(* Logix 5000 project; controller SMD23E2_EDS_AOI_CompactLogix_RSLogix_V28 vendor 1 type 14 code 108 rev 28.11; software revision 28.00; part 2 of 4 *)

ADD_ON_INSTRUCTION AMCI_SMD23E2_Home_CW   (* revision 5.0, vendor AMCI, ExecuteEnableInFalse *)
// Revision note:
// Version 5.0 added the (hidden) ability to program the motor current and unlatched the error bit if the rung goes false.
VAR_INPUT
   Axis_Status_Bits : INT; {required}
   Type_0_for_standard_1_for_indexed : BOOL;
   Programmed_Speed : DINT; {required}
   Acceleration : INT; {required}
   Deceleration : INT; {required}
   motor_current : INT;
   Jerk : INT;
END_VAR
VAR_IN_OUT
   AMCI_SMD23E2_output_data : _000A:SMD23E2_788832CB:O:0; {required}
END_VAR
VAR_OUTPUT
   EN : BOOL; {access Read Only, visible}
   ER : BOOL; {visible}
END_VAR
VAR
   Upper_Result_X_1000 : DINT;
   command_data_block : INT[10];
        [1]   // Command Bits LSW
        [3]   // Lower Target Position
        [5]   // Lower Programmed Speed
        [0]   // Command Bits MSW
        [2]   // Upper Target Position
        [4]   // Upper Programmed Speed
END_VAR

ROUTINE EnableInFalse   (* ladder *)
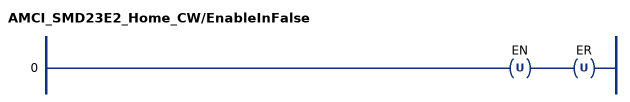
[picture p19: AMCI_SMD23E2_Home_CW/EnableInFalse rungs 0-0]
   0: OTU(EN)OTU(ER);
END_ROUTINE

ROUTINE Logic   (* ladder *)
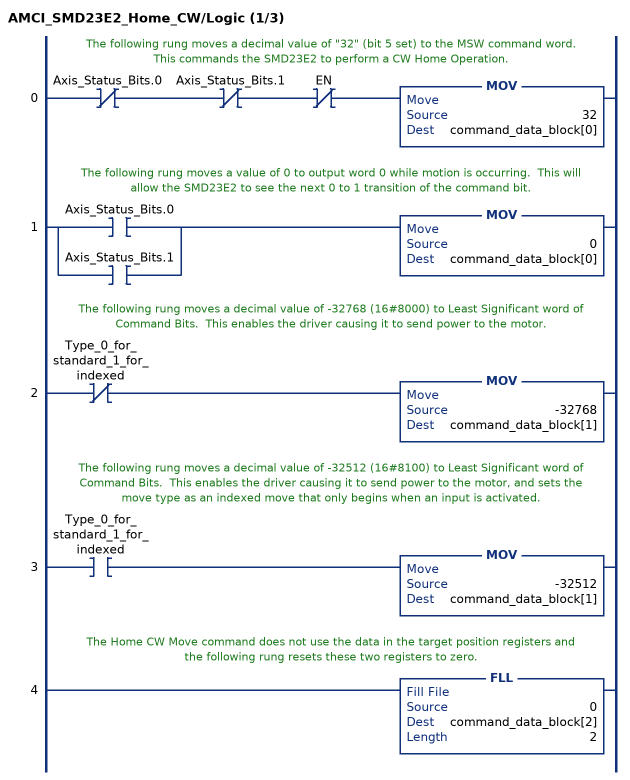
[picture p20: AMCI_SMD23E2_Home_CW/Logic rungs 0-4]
   // The following rung moves a decimal value of "32" (bit 5 set) to the MSW command word.  This commands the SMD23E2 to perform a CW Home Operation.
   0: XIO(Axis_Status_Bits.0)XIO(Axis_Status_Bits.1)XIO(EN)MOV(32,command_data_block[0]);
   // The following rung moves a value of 0 to output word 0 while motion is occurring.  This will allow the SMD23E2 to see the next 0 to 1 transition of the command bit.
   1: [XIC(Axis_Status_Bits.0) ,XIC(Axis_Status_Bits.1) ]MOV(0,command_data_block[0]);
   // The following rung moves a decimal value of -32768 (16#8000) to Least Significant word of Command Bits.  This enables the driver causing it to send power to the motor.
   2: XIO(Type_0_for_standard_1_for_indexed)MOV(-32768,command_data_block[1]);
   // The following rung moves a decimal value of -32512 (16#8100) to Least Significant word of Command Bits.  This enables the driver causing it to send power to the motor, and sets the move type as an indexed move that only begins when an input is activated.
   3: XIC(Type_0_for_standard_1_for_indexed)MOV(-32512,command_data_block[1]);
   // The Home CW Move command does not use the data in the target position registers and the following rung resets these two registers to zero.
   4: FLL(0,command_data_block[2],2);
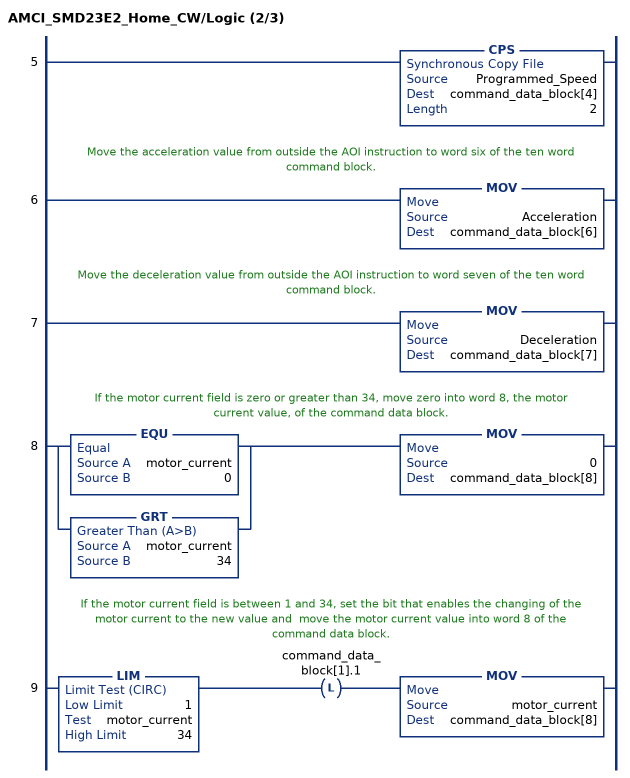
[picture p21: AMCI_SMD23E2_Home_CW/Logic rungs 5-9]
   5: CPS(Programmed_Speed,command_data_block[4],2);
   // Move the acceleration value from outside the AOI instruction to word six of the ten word command block.
   6: MOV(Acceleration,command_data_block[6]);
   // Move the deceleration value from outside the AOI instruction to word seven of the ten word command block.
   7: MOV(Deceleration,command_data_block[7]);
   // If the motor current field is zero or greater than 34, move zero into word 8, the motor current value, of the command data block.
   8: [EQU(motor_current,0) ,GRT(motor_current,34) ]MOV(0,command_data_block[8]);
   // If the motor current field is between 1 and 34, set the bit that enables the changing of the motor current to the new value and  move the motor current value into word 8 of the command data block.
   9: LIM(1,motor_current,34)OTL(command_data_block[1].1)MOV(motor_current,command_data_block[8]);
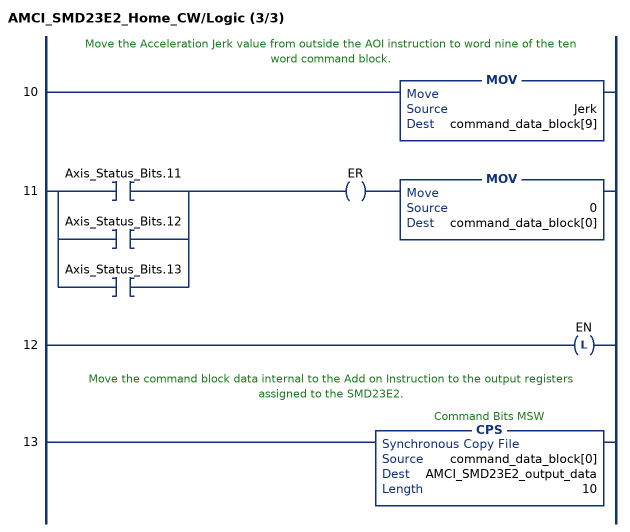
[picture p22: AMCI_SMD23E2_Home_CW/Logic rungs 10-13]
   // Move the Acceleration Jerk value from outside the AOI instruction to word nine of the ten word command block.
   10: MOV(Jerk,command_data_block[9]);
   11: [XIC(Axis_Status_Bits.11) ,XIC(Axis_Status_Bits.12) ,XIC(Axis_Status_Bits.13) ]OTE(ER)MOV(0,command_data_block[0]);
   12: OTL(EN);
   // Move the command block data internal to the Add on Instruction to the output registers assigned to the SMD23E2.
   13: CPS(command_data_block[0],AMCI_SMD23E2_output_data,10);
END_ROUTINE
END_ADD_ON_INSTRUCTION

ADD_ON_INSTRUCTION AMCI_SMD23E2_Immediate_Stop   (* revision 1.0, vendor AMCI *)
VAR_IN_OUT
   AMCI_SMD23E2_output_data : _000A:SMD23E2_788832CB:O:0; {required}
END_VAR
VAR
   command_data_block : INT[10];
        [1]   // Command Bits LSW
        [3]   // Lower Target Position
        [5]   // Lower Programmed Speed
        [0]   // Command Bits MSW
        [2]   // Upper Target Position
        [4]   // Upper Programmed Speed
END_VAR

ROUTINE Logic   (* ladder *)
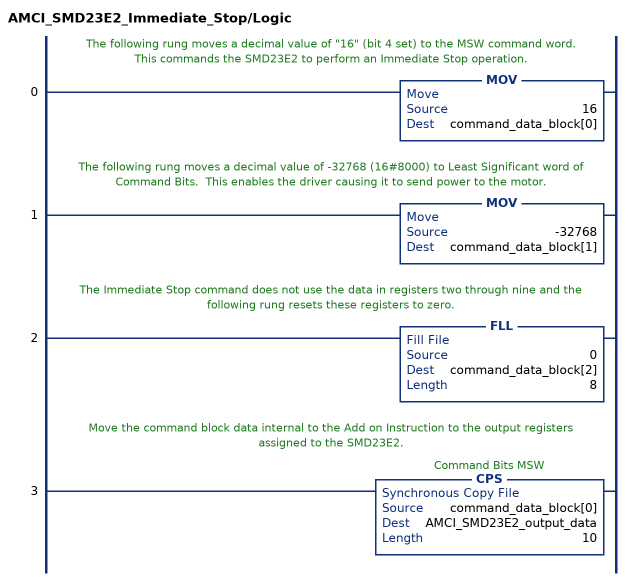
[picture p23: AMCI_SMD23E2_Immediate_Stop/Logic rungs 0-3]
   // The following rung moves a decimal value of "16" (bit 4 set) to the MSW command word.  This commands the SMD23E2 to perform an Immediate Stop operation.
   0: MOV(16,command_data_block[0]);
   // The following rung moves a decimal value of -32768 (16#8000) to Least Significant word of Command Bits.  This enables the driver causing it to send power to the motor.
   1: MOV(-32768,command_data_block[1]);
   // The Immediate Stop command does not use the data in registers two through nine and the following rung resets these registers to zero.
   2: FLL(0,command_data_block[2],8);
   // Move the command block data internal to the Add on Instruction to the output registers assigned to the SMD23E2.
   3: CPS(command_data_block[0],AMCI_SMD23E2_output_data,10);
END_ROUTINE
END_ADD_ON_INSTRUCTION

ADD_ON_INSTRUCTION AMCI_SMD23E2_Jog_CCW   (* revision 5.0, vendor AMCI, ExecuteEnableInFalse *)
// Revision note:
// Version 5.0 added the (hidden) ability to program the motor current and unlatched the error bit if the rung goes false.
VAR_INPUT
   Axis_Status_Bits : INT; {required}
   Programmed_Speed : DINT; {required}
   Acceleration : INT; {required}
   Deceleration : INT; {required}
   motor_current : INT;
   Jerk : INT;
END_VAR
VAR_OUTPUT
   EN : BOOL; {access Read Only, visible}
   Jog_CCW_Occurring : BOOL; {access Read Only, visible}
END_VAR
VAR_IN_OUT
   AMCI_SMD23E2_output_data : _000A:SMD23E2_788832CB:O:0; {required}
END_VAR
VAR_OUTPUT
   ER : BOOL; {access Read Only, visible}
END_VAR
VAR
   Upper_Result_X_1000 : DINT;
   command_data_block : INT[10];
        [1]   // Command Bits LSW
        [3]   // Lower Target Position
        [5]   // Lower Programmed Speed
        [0]   // Command Bits MSW
        [2]   // Upper Target Position
        [4]   // Upper Programmed Speed
END_VAR

ROUTINE EnableInFalse   (* ladder *)
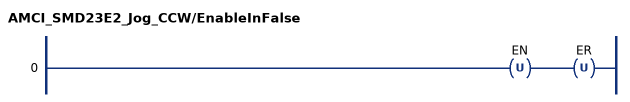
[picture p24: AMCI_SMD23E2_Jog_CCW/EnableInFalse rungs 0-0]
   0: OTU(EN)OTU(ER);
END_ROUTINE

ROUTINE Logic   (* ladder *)
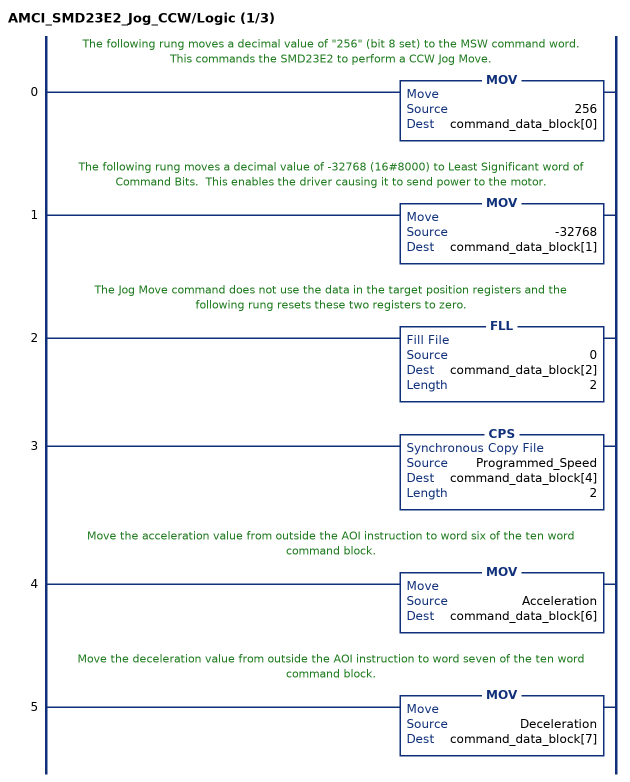
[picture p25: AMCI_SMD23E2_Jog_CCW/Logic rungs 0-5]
   // The following rung moves a decimal value of "256" (bit 8 set) to the MSW command word.  This commands the SMD23E2 to perform a CCW Jog Move.
   0: MOV(256,command_data_block[0]);
   // The following rung moves a decimal value of -32768 (16#8000) to Least Significant word of Command Bits.  This enables the driver causing it to send power to the motor.
   1: MOV(-32768,command_data_block[1]);
   // The Jog Move command does not use the data in the target position registers and the following rung resets these two registers to zero.
   2: FLL(0,command_data_block[2],2);
   3: CPS(Programmed_Speed,command_data_block[4],2);
   // Move the acceleration value from outside the AOI instruction to word six of the ten word command block.
   4: MOV(Acceleration,command_data_block[6]);
   // Move the deceleration value from outside the AOI instruction to word seven of the ten word command block.
   5: MOV(Deceleration,command_data_block[7]);
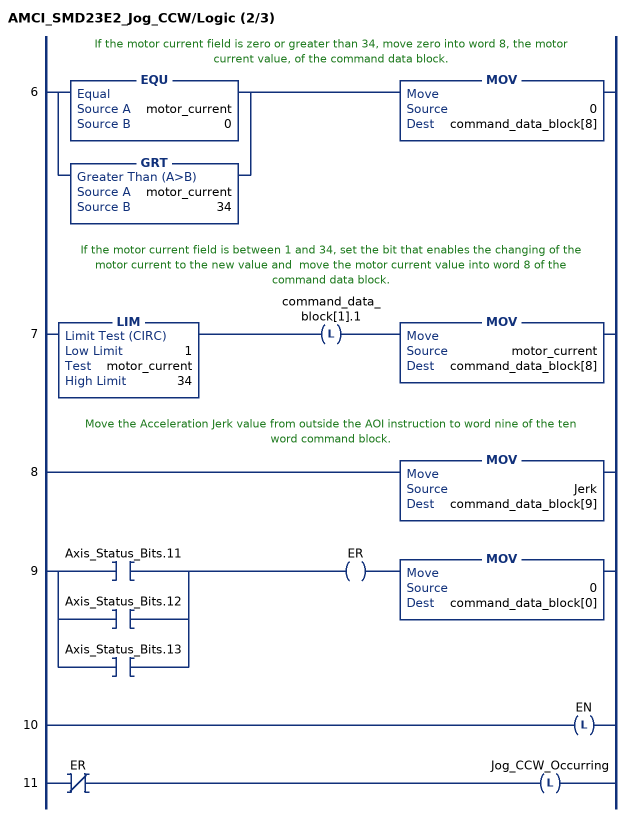
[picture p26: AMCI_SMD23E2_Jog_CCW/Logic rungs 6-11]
   // If the motor current field is zero or greater than 34, move zero into word 8, the motor current value, of the command data block.
   6: [EQU(motor_current,0) ,GRT(motor_current,34) ]MOV(0,command_data_block[8]);
   // If the motor current field is between 1 and 34, set the bit that enables the changing of the motor current to the new value and  move the motor current value into word 8 of the command data block.
   7: LIM(1,motor_current,34)OTL(command_data_block[1].1)MOV(motor_current,command_data_block[8]);
   // Move the Acceleration Jerk value from outside the AOI instruction to word nine of the ten word command block.
   8: MOV(Jerk,command_data_block[9]);
   9: [XIC(Axis_Status_Bits.11) ,XIC(Axis_Status_Bits.12) ,XIC(Axis_Status_Bits.13) ]OTE(ER)MOV(0,command_data_block[0]);
   10: OTL(EN);
   11: XIO(ER)OTL(Jog_CCW_Occurring);
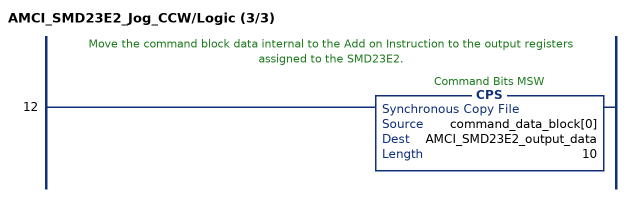
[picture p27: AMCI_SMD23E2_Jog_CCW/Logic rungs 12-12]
   // Move the command block data internal to the Add on Instruction to the output registers assigned to the SMD23E2.
   12: CPS(command_data_block[0],AMCI_SMD23E2_output_data,10);
END_ROUTINE
END_ADD_ON_INSTRUCTION

ADD_ON_INSTRUCTION AMCI_SMD23E2_Jog_CW   (* revision 5.0, vendor AMCI, ExecuteEnableInFalse *)
// Revision note:
// Version 5.0 added the (hidden) ability to program the motor current and unlatched the error bit if the rung goes false.
VAR_INPUT
   Axis_Status_Bits : INT; {required}
   Programmed_Speed : DINT; {required}
   Acceleration : INT; {required}
   Deceleration : INT; {required}
   motor_current : INT;
   Jerk : INT;
END_VAR
VAR_OUTPUT
   EN : BOOL; {access Read Only, visible}
   Jog_CW_Occurring : BOOL; {access Read Only, visible}
END_VAR
VAR_IN_OUT
   AMCI_SMD23E2_output_data : _000A:SMD23E2_788832CB:O:0; {required}
END_VAR
VAR_OUTPUT
   ER : BOOL; {access Read Only, visible}
END_VAR
VAR
   Upper_Result_X_1000 : DINT;
   command_data_block : INT[10];
        [1]   // Command Bits LSW
        [3]   // Lower Target Position
        [5]   // Lower Programmed Speed
        [0]   // Command Bits MSW
        [2]   // Upper Target Position
        [4]   // Upper Programmed Speed
END_VAR

ROUTINE EnableInFalse   (* ladder *)
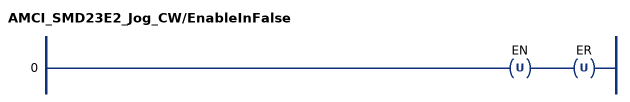
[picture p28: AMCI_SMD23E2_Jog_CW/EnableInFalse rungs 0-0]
   0: OTU(EN)OTU(ER);
END_ROUTINE

ROUTINE Logic   (* ladder *)
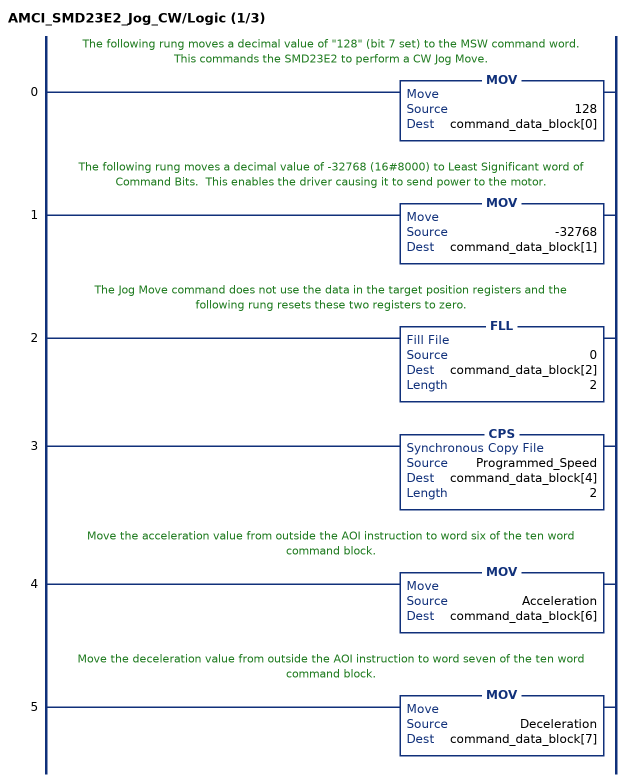
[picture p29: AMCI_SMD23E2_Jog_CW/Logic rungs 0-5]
   // The following rung moves a decimal value of "128" (bit 7 set) to the MSW command word.  This commands the SMD23E2 to perform a CW Jog Move.
   0: MOV(128,command_data_block[0]);
   // The following rung moves a decimal value of -32768 (16#8000) to Least Significant word of Command Bits.  This enables the driver causing it to send power to the motor.
   1: MOV(-32768,command_data_block[1]);
   // The Jog Move command does not use the data in the target position registers and the following rung resets these two registers to zero.
   2: FLL(0,command_data_block[2],2);
   3: CPS(Programmed_Speed,command_data_block[4],2);
   // Move the acceleration value from outside the AOI instruction to word six of the ten word command block.
   4: MOV(Acceleration,command_data_block[6]);
   // Move the deceleration value from outside the AOI instruction to word seven of the ten word command block.
   5: MOV(Deceleration,command_data_block[7]);
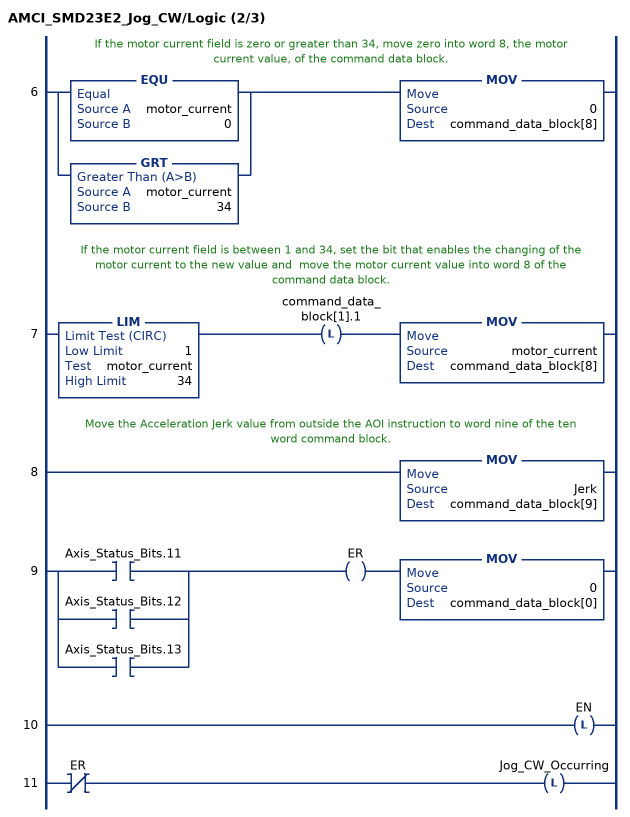
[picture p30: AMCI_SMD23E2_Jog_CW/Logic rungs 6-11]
   // If the motor current field is zero or greater than 34, move zero into word 8, the motor current value, of the command data block.
   6: [EQU(motor_current,0) ,GRT(motor_current,34) ]MOV(0,command_data_block[8]);
   // If the motor current field is between 1 and 34, set the bit that enables the changing of the motor current to the new value and  move the motor current value into word 8 of the command data block.
   7: LIM(1,motor_current,34)OTL(command_data_block[1].1)MOV(motor_current,command_data_block[8]);
   // Move the Acceleration Jerk value from outside the AOI instruction to word nine of the ten word command block.
   8: MOV(Jerk,command_data_block[9]);
   9: [XIC(Axis_Status_Bits.11) ,XIC(Axis_Status_Bits.12) ,XIC(Axis_Status_Bits.13) ]OTE(ER)MOV(0,command_data_block[0]);
   10: OTL(EN);
   11: XIO(ER)OTL(Jog_CW_Occurring);
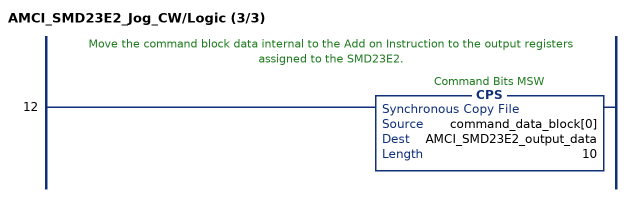
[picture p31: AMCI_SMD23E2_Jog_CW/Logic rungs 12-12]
   // Move the command block data internal to the Add on Instruction to the output registers assigned to the SMD23E2.
   12: CPS(command_data_block[0],AMCI_SMD23E2_output_data,10);
END_ROUTINE
END_ADD_ON_INSTRUCTION

ADD_ON_INSTRUCTION AMCI_SMD23E2_Preset_Encoder_Position   (* revision 1.0, vendor AMCI *)
VAR_INPUT
   save_in_flash_0_no_1_yes : BOOL; {required}
   Target_Position : DINT; {required}
END_VAR
VAR_IN_OUT
   AMCI_SMD23E2_output_data : _000A:SMD23E2_788832CB:O:0; {required}
END_VAR
VAR
   Upper_Result_X_1000 : DINT;
   command_data_block : INT[10];
        [1]   // Command Bits LSW
        [3]   // Lower Target Position
        [5]   // Lower Programmed Speed
        [0]   // Command Bits MSW
        [2]   // Upper Target Position
        [4]   // Upper Programmed Speed
END_VAR

ROUTINE Logic   (* ladder *)
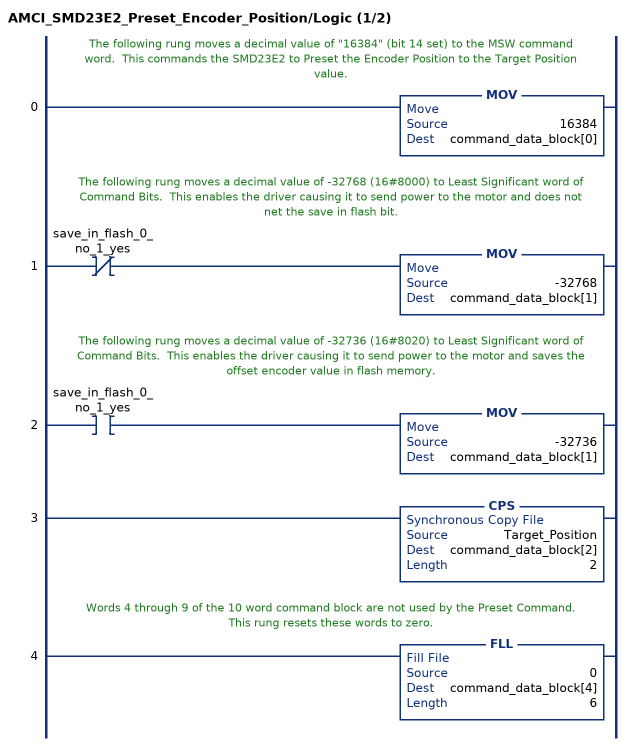
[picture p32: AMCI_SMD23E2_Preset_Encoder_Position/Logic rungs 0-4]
   // The following rung moves a decimal value of "16384" (bit 14 set) to the MSW command word.  This commands the SMD23E2 to Preset the Encoder Position to the Target Position value.
   0: MOV(16384,command_data_block[0]);
   // The following rung moves a decimal value of -32768 (16#8000) to Least Significant word of Command Bits.  This enables the driver causing it to send power to the motor and does not net the save in flash bit.
   1: XIO(save_in_flash_0_no_1_yes)MOV(-32768,command_data_block[1]);
   // The following rung moves a decimal value of -32736 (16#8020) to Least Significant word of Command Bits.  This enables the driver causing it to send power to the motor and saves the offset encoder value in flash memory.
   2: XIC(save_in_flash_0_no_1_yes)MOV(-32736,command_data_block[1]);
   3: CPS(Target_Position,command_data_block[2],2);
   // Words 4 through 9 of the 10 word command block are not used by the Preset Command.  This rung resets these words to zero.
   4: FLL(0,command_data_block[4],6);
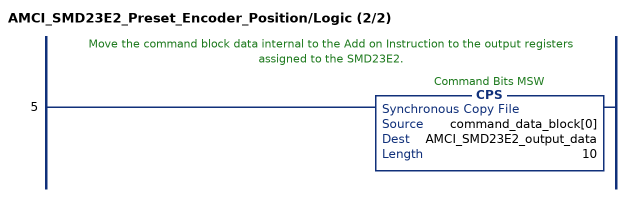
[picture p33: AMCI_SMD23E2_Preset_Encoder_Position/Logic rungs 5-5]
   // Move the command block data internal to the Add on Instruction to the output registers assigned to the SMD23E2.
   5: CPS(command_data_block[0],AMCI_SMD23E2_output_data,10);
END_ROUTINE
END_ADD_ON_INSTRUCTION

ADD_ON_INSTRUCTION AMCI_SMD23E2_Preset_Motor_Position   (* revision 1.0, vendor AMCI *)
VAR_INPUT
   Target_Position : DINT; {required}
END_VAR
VAR_IN_OUT
   AMCI_SMD23E2_output_data : _000A:SMD23E2_788832CB:O:0; {required}
END_VAR
VAR
   Upper_Result_X_1000 : DINT;
   command_data_block : INT[10];
        [1]   // Command Bits LSW
        [3]   // Lower Target Position
        [5]   // Lower Programmed Speed
        [2]   // Upper Target Position
        [4]   // Upper Programmed Speed
        [0]   // Command Bits MSW
END_VAR

ROUTINE Logic   (* ladder *)
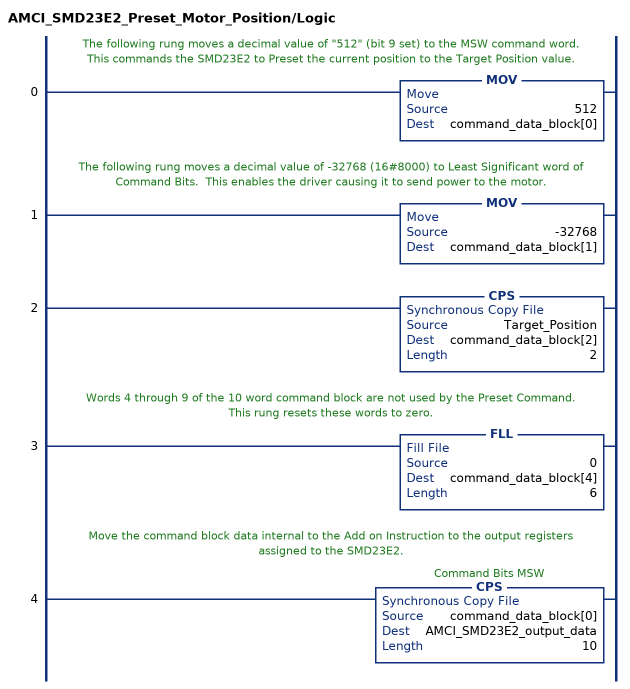
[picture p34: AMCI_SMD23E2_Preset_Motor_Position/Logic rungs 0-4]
   // The following rung moves a decimal value of "512" (bit 9 set) to the MSW command word.  This commands the SMD23E2 to Preset the current position to the Target Position value.
   0: MOV(512,command_data_block[0]);
   // The following rung moves a decimal value of -32768 (16#8000) to Least Significant word of Command Bits.  This enables the driver causing it to send power to the motor.
   1: MOV(-32768,command_data_block[1]);
   2: CPS(Target_Position,command_data_block[2],2);
   // Words 4 through 9 of the 10 word command block are not used by the Preset Command.  This rung resets these words to zero.
   3: FLL(0,command_data_block[4],6);
   // Move the command block data internal to the Add on Instruction to the output registers assigned to the SMD23E2.
   4: CPS(command_data_block[0],AMCI_SMD23E2_output_data,10);
END_ROUTINE
END_ADD_ON_INSTRUCTION

ADD_ON_INSTRUCTION AMCI_SMD23E2_Preset_Motor_to_Encoder   (* revision 1.0, vendor AMCI *)
VAR_IN_OUT
   AMCI_SMD23E2_output_data : _000A:SMD23E2_788832CB:O:0; {required}
END_VAR
VAR
   Upper_Result_X_1000 : DINT;
   command_data_block : INT[10];
        [1]   // Command Bits LSW
        [3]   // Lower Target Position
        [5]   // Lower Programmed Speed
        [0]   // Command Bits MSW
        [2]   // Upper Target Position
        [4]   // Upper Programmed Speed
END_VAR

ROUTINE Logic   (* ladder *)
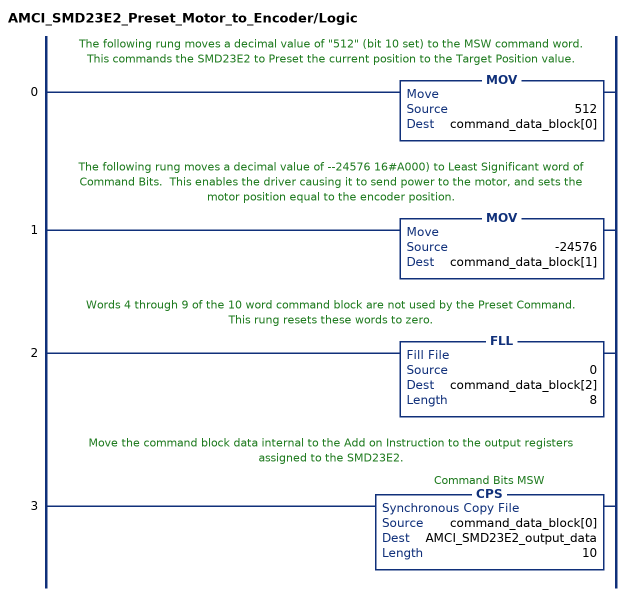
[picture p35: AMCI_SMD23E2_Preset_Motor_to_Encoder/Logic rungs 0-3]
   // The following rung moves a decimal value of "512" (bit 10 set) to the MSW command word.  This commands the SMD23E2 to Preset the current position to the Target Position value.
   0: MOV(512,command_data_block[0]);
   // The following rung moves a decimal value of --24576 16#A000) to Least Significant word of Command Bits.  This enables the driver causing it to send power to the motor, and sets the motor position equal to the encoder position.
   1: MOV(-24576,command_data_block[1]);
   // Words 4 through 9 of the 10 word command block are not used by the Preset Command.  This rung resets these words to zero.
   2: FLL(0,command_data_block[2],8);
   // Move the command block data internal to the Add on Instruction to the output registers assigned to the SMD23E2.
   3: CPS(command_data_block[0],AMCI_SMD23E2_output_data,10);
END_ROUTINE
END_ADD_ON_INSTRUCTION

ADD_ON_INSTRUCTION AMCI_SMD23E2_Program_Assembed_Move   (* revision 1.0, vendor AMCI *)
VAR_INPUT
   Axis_Status_Bits : INT; {required}
        .8   // set when SMD23E2 is in Assembled Move mode
        .9   // set when the SMD23E2 is ready to receive an assembled move segment
   Number_of_Segments : DINT; {required}
   Segment_1_Distance : DINT; {required}
   Segment_1_Programmed_Speed : DINT; {required}
   Segment_1_Acceleration : INT; {required}
   Segment_1_Deceleration : INT; {required}
   Segment_2_Distance : DINT; {required}
   Segment_2_Programmed_Speed : DINT; {required}
   Segment_2_Acceleration : INT; {required}
   Segment_2_Deceleration : INT; {required}
   Segment_3_Distance : DINT; {required}
   Segment_3_Programmed_Speed : DINT; {required}
   Segment_3_Acceleration : INT; {required}
   Segment_3_Deceleration : INT; {required}
   Segment_4_Distance : DINT; {required}
   Segment_4_Programmed_Speed : DINT; {required}
   Segment_4_Acceleration : INT; {required}
   Segment_4_Deceleration : INT; {required}
   Segment_5_Distance : DINT; {required}
   Segment_5_Programmed_Speed : DINT; {required}
   Segment_5_Acceleration : INT; {required}
   Segment_5_Deceleration : INT; {required}
   Segment_6_Distance : DINT; {required}
   Segment_6_Programmed_Speed : DINT; {required}
   Segment_6_Acceleration : INT; {required}
   Segment_6_Deceleration : INT; {required}
   Segment_7_Distance : DINT; {required}
   Segment_7_Programmed_Speed : DINT; {required}
   Segment_7_Acceleration : INT; {required}
   Segment_7_Deceleration : INT; {required}
   Segment_8_Distance : DINT; {required}
   Segment_8_Programmed_Speed : DINT; {required}
   Segment_8_Acceleration : INT; {required}
   Segment_8_Deceleration : INT; {required}
   Segment_9_Distance : DINT; {required}
   Segment_9_Programmed_Speed : DINT; {required}
   Segment_9_Acceleration : INT; {required}
   Segment_9_Deceleration : INT; {required}
   Segment_10_Distance : DINT; {required}
   Segment_10_Programmed_Speed : DINT; {required}
   Segment_10_Acceleration : INT; {required}
   Segment_10_Deceleration : INT; {required}
   Segment_11_Distance : DINT; {required}
   Segment_11_Programmed_Speed : DINT; {required}
   Segment_11_Acceleration : INT; {required}
   Segment_11_Deceleration : INT; {required}
   Segment_12_Distance : DINT; {required}
   Segment_12_Programmed_Speed : DINT; {required}
   Segment_12_Acceleration : INT; {required}
   Segment_12_Deceleration : INT; {required}
   Segment_13_Distance : DINT; {required}
   Segment_13_Programmed_Speed : DINT; {required}
   Segment_13_Acceleration : INT; {required}
   Segment_13_Deceleration : INT; {required}
   Segment_14_Distance : DINT; {required}
   Segment_14_Programmed_Speed : DINT; {required}
   Segment_14_Acceleration : INT; {required}
   Segment_14_Deceleration : INT; {required}
   Segment_15_Distance : DINT; {required}
   Segment_15_Programmed_Speed : DINT; {required}
   Segment_15_Acceleration : INT; {required}
   Segment_15_Deceleration : INT; {required}
   Segment_16_Distance : DINT; {required}
   Segment_16_Programmed_Speed : DINT; {required}
   Segment_16_Acceleration : INT; {required}
   Segment_16_Deceleration : INT; {required}
END_VAR
VAR_IN_OUT
   AMCI_SMD23E2_output_data : _000A:SMD23E2_788832CB:O:0; {required}
END_VAR
VAR_OUTPUT
   Assembled_Move_Programmed : BOOL; {access Read Only, visible}
END_VAR
VAR
   command_data_block : INT[10];
        [1]   // Command Bits LSW
        [5]   // Lower Programmed Speed
        [2]   // Upper Target Position
        [4]   // Upper Programmed Speed
        [3]   // Lower Target Position
        [0]   // Command Bits MSW
   Assembled_Move_setup : INT[10] := ([0] := 2048, [1] := -32768); {access None}
   Assembled_Move_counter : COUNTER := (PRE := 5); {access None}
        .ACC   // Controls which segment is sent to the SMD23E2
   comment_coil : BOOL; {access None}
END_VAR

ROUTINE Logic   (* ladder *)
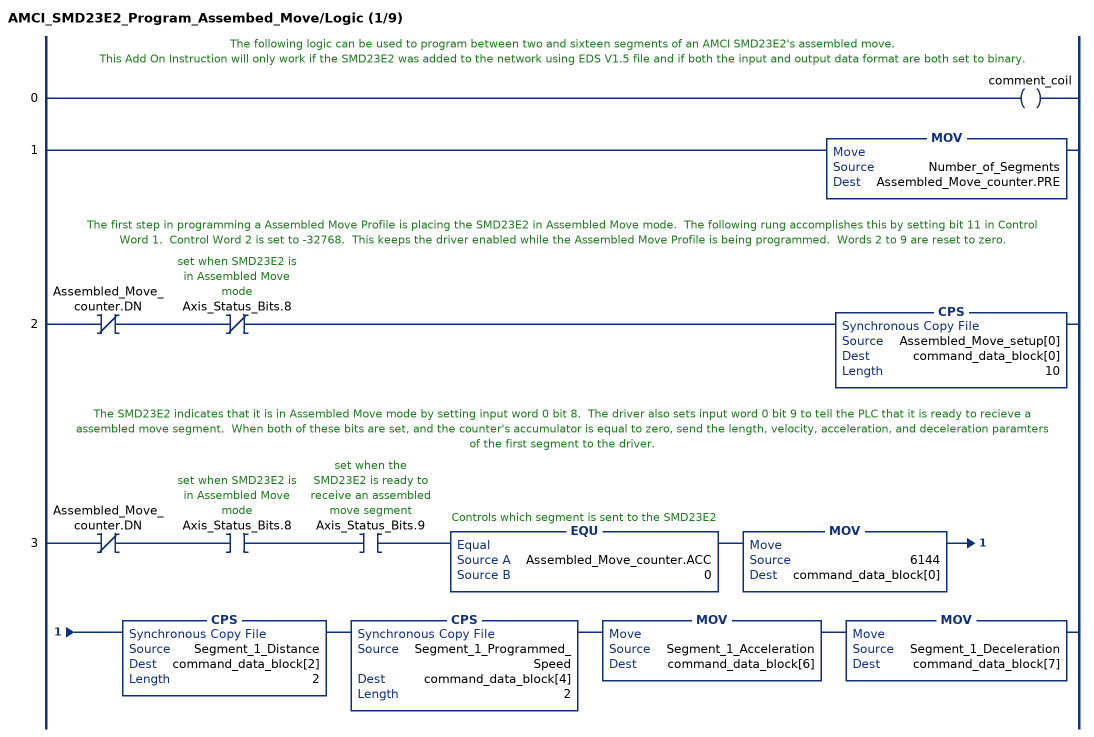
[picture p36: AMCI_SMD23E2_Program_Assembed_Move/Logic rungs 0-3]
   // The following logic can be used to program between two and sixteen segments of an AMCI SMD23E2's assembled move.
   // This Add On Instruction will only work if the SMD23E2 was added to the network using EDS V1.5 file and if both the input and output data format are both set to binary.
   0: OTE(comment_coil);
   1: MOV(Number_of_Segments,Assembled_Move_counter.PRE);
   // The first step in programming a Assembled Move Profile is placing the SMD23E2 in Assembled Move mode.  The following rung accomplishes this by setting bit 11 in Control Word 1.  Control Word 2 is set to -32768.  This keeps the driver enabled while the Assembled Move Profile is being programmed.  Words 2 to 9 are reset to zero.
   2: XIO(Assembled_Move_counter.DN)XIO(Axis_Status_Bits.8)CPS(Assembled_Move_setup[0],command_data_block[0],10);
   // The SMD23E2 indicates that it is in Assembled Move mode by setting input word 0 bit 8.  The driver also sets input word 0 bit 9 to tell the PLC that it is ready to recieve a assembled move segment.  When both of these bits are set, and the counter's accumulator is equal to zero, send the length, velocity, acceleration, and deceleration paramters of the first segment to the driver.
   3: XIO(Assembled_Move_counter.DN)XIC(Axis_Status_Bits.8)XIC(Axis_Status_Bits.9)EQU(Assembled_Move_counter.ACC,0)MOV(6144,command_data_block[0])CPS(Segment_1_Distance,command_data_block[2],2)CPS(Segment_1_Programmed_Speed,command_data_block[4],2)MOV(Segment_1_Acceleration,command_data_block[6])MOV(Segment_1_Deceleration,command_data_block[7]);
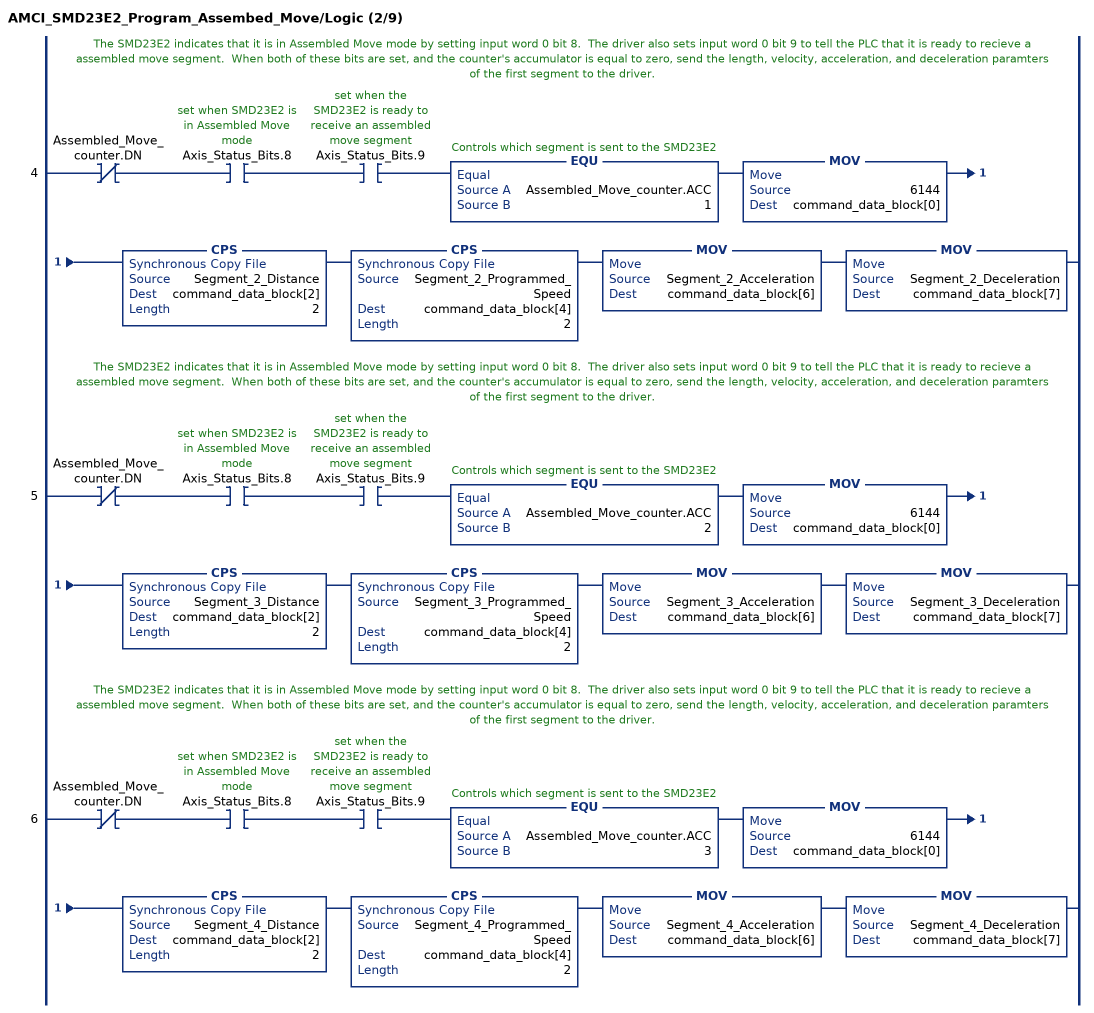
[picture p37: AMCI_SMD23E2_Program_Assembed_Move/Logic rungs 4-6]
   // The SMD23E2 indicates that it is in Assembled Move mode by setting input word 0 bit 8.  The driver also sets input word 0 bit 9 to tell the PLC that it is ready to recieve a assembled move segment.  When both of these bits are set, and the counter's accumulator is equal to zero, send the length, velocity, acceleration, and deceleration paramters of the first segment to the driver.
   4: XIO(Assembled_Move_counter.DN)XIC(Axis_Status_Bits.8)XIC(Axis_Status_Bits.9)EQU(Assembled_Move_counter.ACC,1)MOV(6144,command_data_block[0])CPS(Segment_2_Distance,command_data_block[2],2)CPS(Segment_2_Programmed_Speed,command_data_block[4],2)MOV(Segment_2_Acceleration,command_data_block[6])MOV(Segment_2_Deceleration,command_data_block[7]);
   // The SMD23E2 indicates that it is in Assembled Move mode by setting input word 0 bit 8.  The driver also sets input word 0 bit 9 to tell the PLC that it is ready to recieve a assembled move segment.  When both of these bits are set, and the counter's accumulator is equal to zero, send the length, velocity, acceleration, and deceleration paramters of the first segment to the driver.
   5: XIO(Assembled_Move_counter.DN)XIC(Axis_Status_Bits.8)XIC(Axis_Status_Bits.9)EQU(Assembled_Move_counter.ACC,2)MOV(6144,command_data_block[0])CPS(Segment_3_Distance,command_data_block[2],2)CPS(Segment_3_Programmed_Speed,command_data_block[4],2)MOV(Segment_3_Acceleration,command_data_block[6])MOV(Segment_3_Deceleration,command_data_block[7]);
   // The SMD23E2 indicates that it is in Assembled Move mode by setting input word 0 bit 8.  The driver also sets input word 0 bit 9 to tell the PLC that it is ready to recieve a assembled move segment.  When both of these bits are set, and the counter's accumulator is equal to zero, send the length, velocity, acceleration, and deceleration paramters of the first segment to the driver.
   6: XIO(Assembled_Move_counter.DN)XIC(Axis_Status_Bits.8)XIC(Axis_Status_Bits.9)EQU(Assembled_Move_counter.ACC,3)MOV(6144,command_data_block[0])CPS(Segment_4_Distance,command_data_block[2],2)CPS(Segment_4_Programmed_Speed,command_data_block[4],2)MOV(Segment_4_Acceleration,command_data_block[6])MOV(Segment_4_Deceleration,command_data_block[7]);
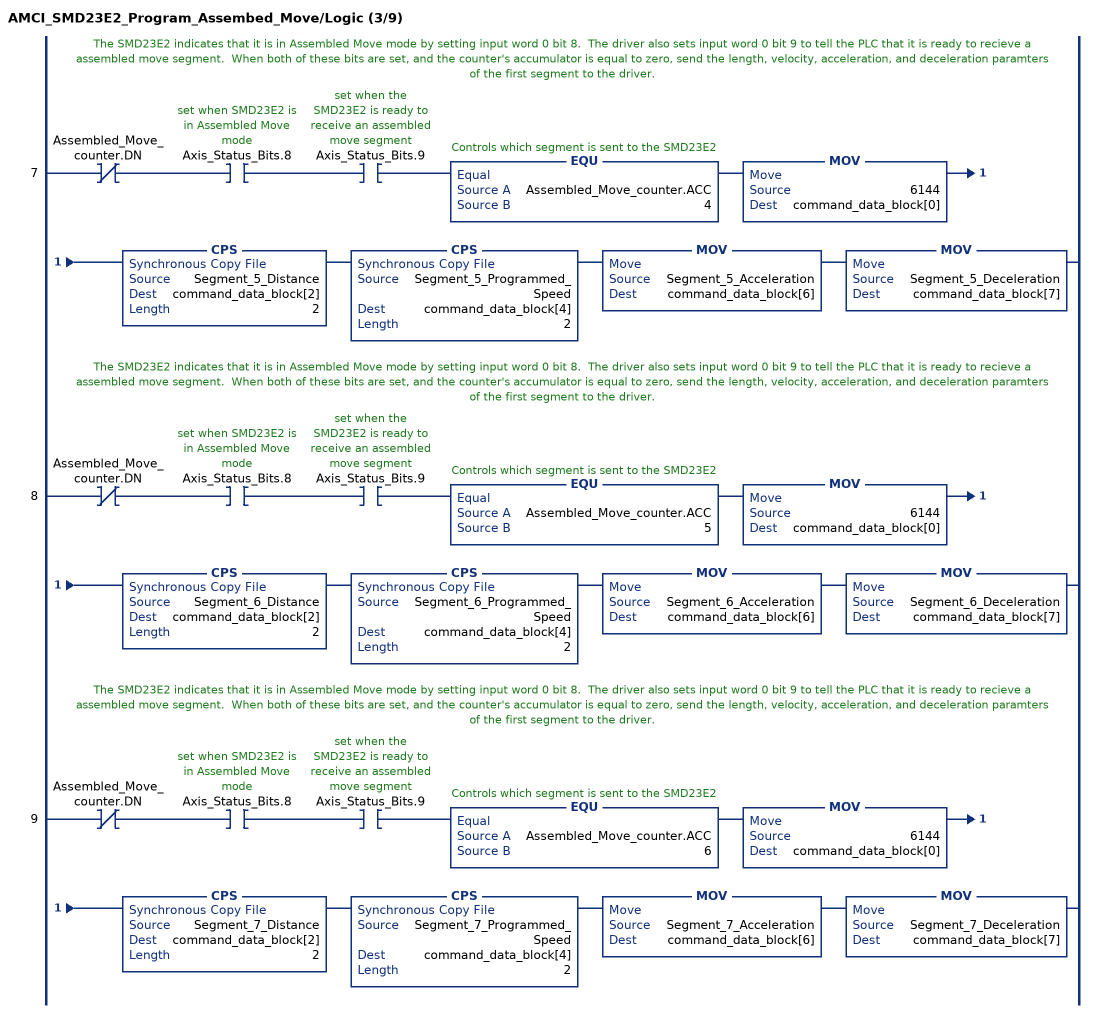
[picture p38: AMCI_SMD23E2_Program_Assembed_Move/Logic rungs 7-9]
   // The SMD23E2 indicates that it is in Assembled Move mode by setting input word 0 bit 8.  The driver also sets input word 0 bit 9 to tell the PLC that it is ready to recieve a assembled move segment.  When both of these bits are set, and the counter's accumulator is equal to zero, send the length, velocity, acceleration, and deceleration paramters of the first segment to the driver.
   7: XIO(Assembled_Move_counter.DN)XIC(Axis_Status_Bits.8)XIC(Axis_Status_Bits.9)EQU(Assembled_Move_counter.ACC,4)MOV(6144,command_data_block[0])CPS(Segment_5_Distance,command_data_block[2],2)CPS(Segment_5_Programmed_Speed,command_data_block[4],2)MOV(Segment_5_Acceleration,command_data_block[6])MOV(Segment_5_Deceleration,command_data_block[7]);
   // The SMD23E2 indicates that it is in Assembled Move mode by setting input word 0 bit 8.  The driver also sets input word 0 bit 9 to tell the PLC that it is ready to recieve a assembled move segment.  When both of these bits are set, and the counter's accumulator is equal to zero, send the length, velocity, acceleration, and deceleration paramters of the first segment to the driver.
   8: XIO(Assembled_Move_counter.DN)XIC(Axis_Status_Bits.8)XIC(Axis_Status_Bits.9)EQU(Assembled_Move_counter.ACC,5)MOV(6144,command_data_block[0])CPS(Segment_6_Distance,command_data_block[2],2)CPS(Segment_6_Programmed_Speed,command_data_block[4],2)MOV(Segment_6_Acceleration,command_data_block[6])MOV(Segment_6_Deceleration,command_data_block[7]);
   // The SMD23E2 indicates that it is in Assembled Move mode by setting input word 0 bit 8.  The driver also sets input word 0 bit 9 to tell the PLC that it is ready to recieve a assembled move segment.  When both of these bits are set, and the counter's accumulator is equal to zero, send the length, velocity, acceleration, and deceleration paramters of the first segment to the driver.
   9: XIO(Assembled_Move_counter.DN)XIC(Axis_Status_Bits.8)XIC(Axis_Status_Bits.9)EQU(Assembled_Move_counter.ACC,6)MOV(6144,command_data_block[0])CPS(Segment_7_Distance,command_data_block[2],2)CPS(Segment_7_Programmed_Speed,command_data_block[4],2)MOV(Segment_7_Acceleration,command_data_block[6])MOV(Segment_7_Deceleration,command_data_block[7]);
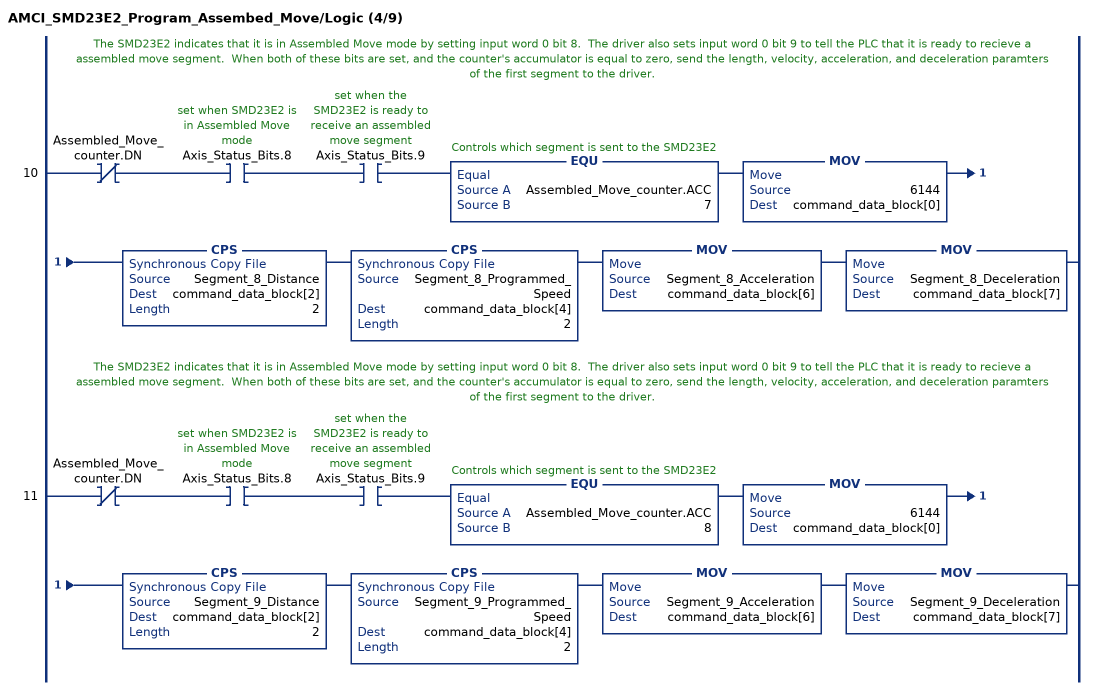
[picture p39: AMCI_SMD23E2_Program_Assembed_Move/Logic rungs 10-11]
   // The SMD23E2 indicates that it is in Assembled Move mode by setting input word 0 bit 8.  The driver also sets input word 0 bit 9 to tell the PLC that it is ready to recieve a assembled move segment.  When both of these bits are set, and the counter's accumulator is equal to zero, send the length, velocity, acceleration, and deceleration paramters of the first segment to the driver.
   10: XIO(Assembled_Move_counter.DN)XIC(Axis_Status_Bits.8)XIC(Axis_Status_Bits.9)EQU(Assembled_Move_counter.ACC,7)MOV(6144,command_data_block[0])CPS(Segment_8_Distance,command_data_block[2],2)CPS(Segment_8_Programmed_Speed,command_data_block[4],2)MOV(Segment_8_Acceleration,command_data_block[6])MOV(Segment_8_Deceleration,command_data_block[7]);
   // The SMD23E2 indicates that it is in Assembled Move mode by setting input word 0 bit 8.  The driver also sets input word 0 bit 9 to tell the PLC that it is ready to recieve a assembled move segment.  When both of these bits are set, and the counter's accumulator is equal to zero, send the length, velocity, acceleration, and deceleration paramters of the first segment to the driver.
   11: XIO(Assembled_Move_counter.DN)XIC(Axis_Status_Bits.8)XIC(Axis_Status_Bits.9)EQU(Assembled_Move_counter.ACC,8)MOV(6144,command_data_block[0])CPS(Segment_9_Distance,command_data_block[2],2)CPS(Segment_9_Programmed_Speed,command_data_block[4],2)MOV(Segment_9_Acceleration,command_data_block[6])MOV(Segment_9_Deceleration,command_data_block[7]);
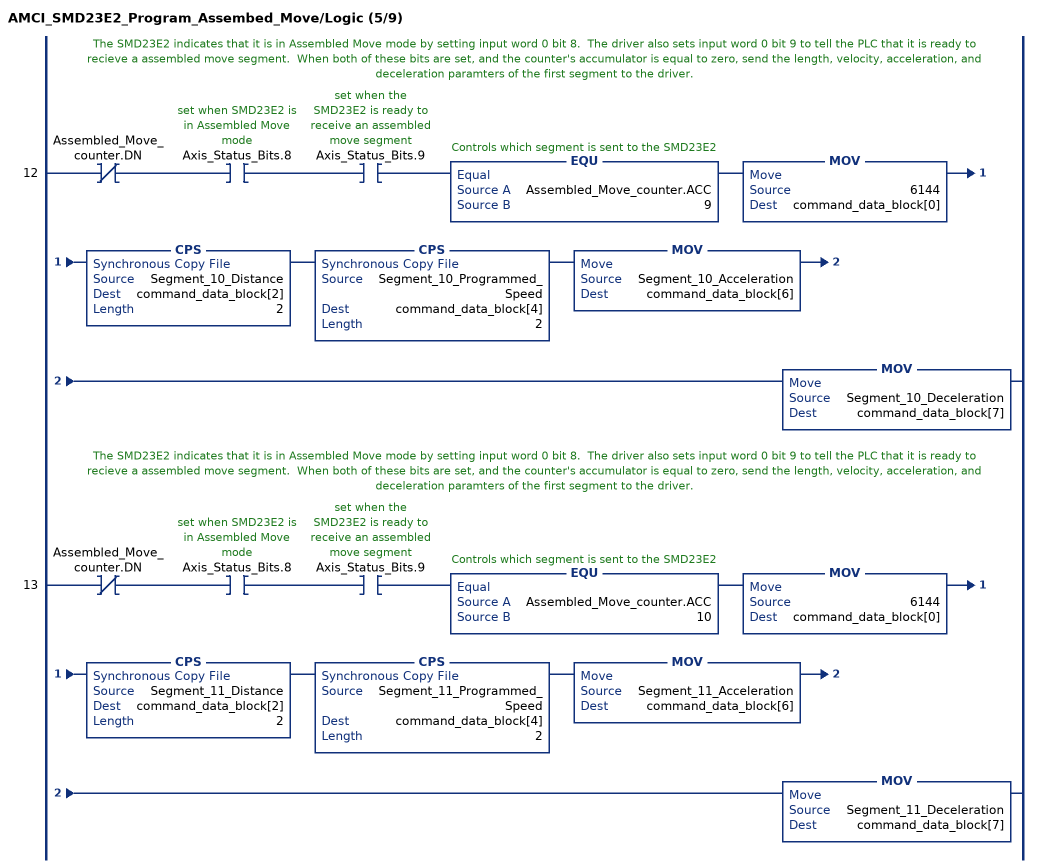
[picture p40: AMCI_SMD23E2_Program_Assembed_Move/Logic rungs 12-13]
   // The SMD23E2 indicates that it is in Assembled Move mode by setting input word 0 bit 8.  The driver also sets input word 0 bit 9 to tell the PLC that it is ready to recieve a assembled move segment.  When both of these bits are set, and the counter's accumulator is equal to zero, send the length, velocity, acceleration, and deceleration paramters of the first segment to the driver.
   12: XIO(Assembled_Move_counter.DN)XIC(Axis_Status_Bits.8)XIC(Axis_Status_Bits.9)EQU(Assembled_Move_counter.ACC,9)MOV(6144,command_data_block[0])CPS(Segment_10_Distance,command_data_block[2],2)CPS(Segment_10_Programmed_Speed,command_data_block[4],2)MOV(Segment_10_Acceleration,command_data_block[6])MOV(Segment_10_Deceleration,command_data_block[7]);
   // The SMD23E2 indicates that it is in Assembled Move mode by setting input word 0 bit 8.  The driver also sets input word 0 bit 9 to tell the PLC that it is ready to recieve a assembled move segment.  When both of these bits are set, and the counter's accumulator is equal to zero, send the length, velocity, acceleration, and deceleration paramters of the first segment to the driver.
   13: XIO(Assembled_Move_counter.DN)XIC(Axis_Status_Bits.8)XIC(Axis_Status_Bits.9)EQU(Assembled_Move_counter.ACC,10)MOV(6144,command_data_block[0])CPS(Segment_11_Distance,command_data_block[2],2)CPS(Segment_11_Programmed_Speed,command_data_block[4],2)MOV(Segment_11_Acceleration,command_data_block[6])MOV(Segment_11_Deceleration,command_data_block[7]);
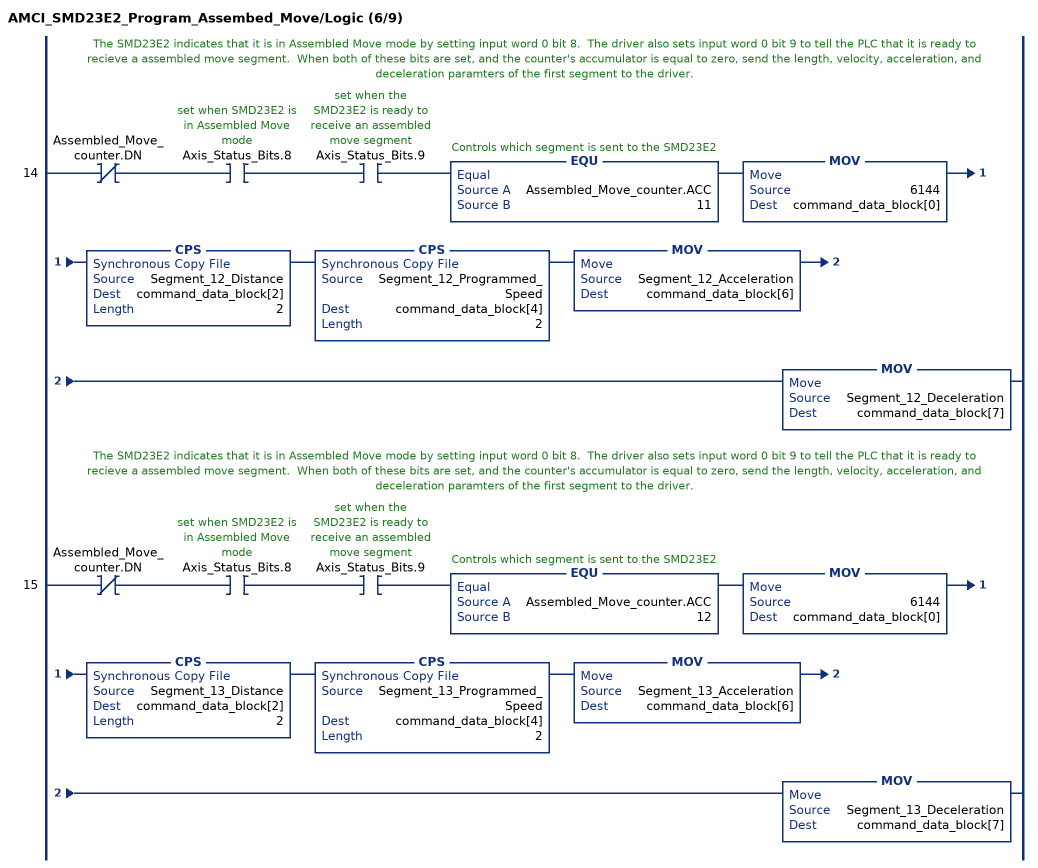
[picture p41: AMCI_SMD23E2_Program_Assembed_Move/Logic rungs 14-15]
   // The SMD23E2 indicates that it is in Assembled Move mode by setting input word 0 bit 8.  The driver also sets input word 0 bit 9 to tell the PLC that it is ready to recieve a assembled move segment.  When both of these bits are set, and the counter's accumulator is equal to zero, send the length, velocity, acceleration, and deceleration paramters of the first segment to the driver.
   14: XIO(Assembled_Move_counter.DN)XIC(Axis_Status_Bits.8)XIC(Axis_Status_Bits.9)EQU(Assembled_Move_counter.ACC,11)MOV(6144,command_data_block[0])CPS(Segment_12_Distance,command_data_block[2],2)CPS(Segment_12_Programmed_Speed,command_data_block[4],2)MOV(Segment_12_Acceleration,command_data_block[6])MOV(Segment_12_Deceleration,command_data_block[7]);
   // The SMD23E2 indicates that it is in Assembled Move mode by setting input word 0 bit 8.  The driver also sets input word 0 bit 9 to tell the PLC that it is ready to recieve a assembled move segment.  When both of these bits are set, and the counter's accumulator is equal to zero, send the length, velocity, acceleration, and deceleration paramters of the first segment to the driver.
   15: XIO(Assembled_Move_counter.DN)XIC(Axis_Status_Bits.8)XIC(Axis_Status_Bits.9)EQU(Assembled_Move_counter.ACC,12)MOV(6144,command_data_block[0])CPS(Segment_13_Distance,command_data_block[2],2)CPS(Segment_13_Programmed_Speed,command_data_block[4],2)MOV(Segment_13_Acceleration,command_data_block[6])MOV(Segment_13_Deceleration,command_data_block[7]);
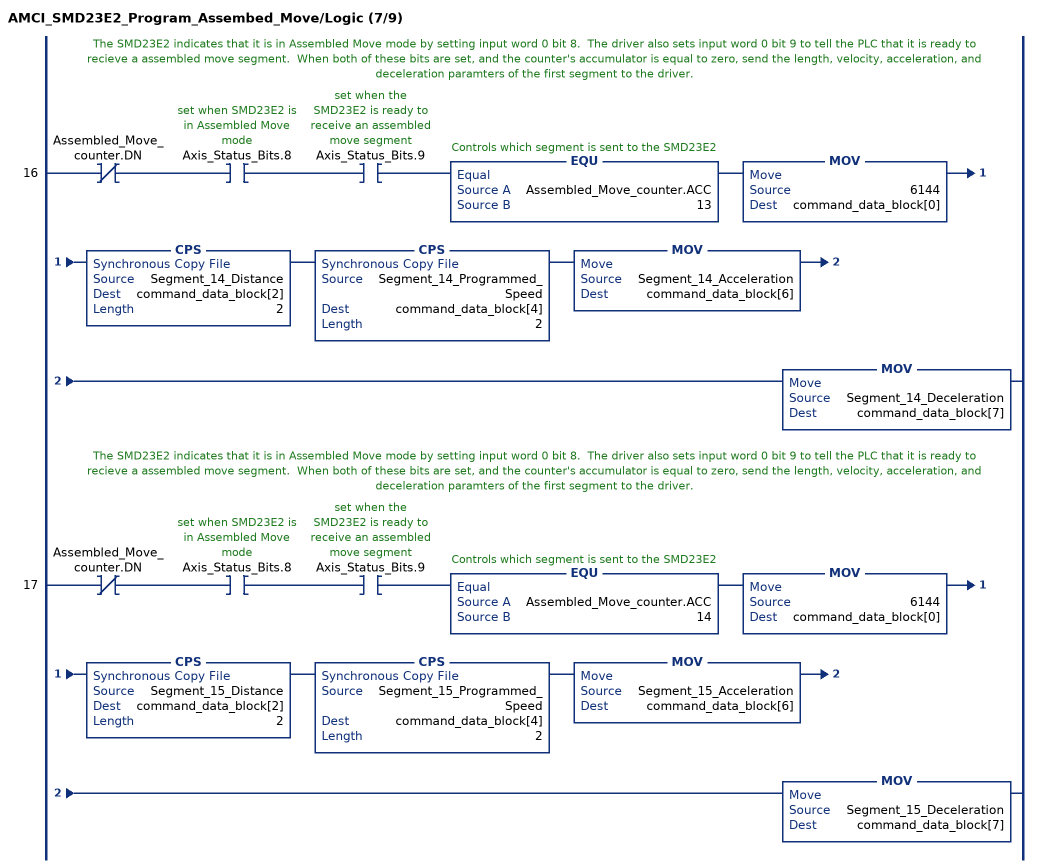
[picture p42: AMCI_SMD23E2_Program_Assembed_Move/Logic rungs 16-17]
   // The SMD23E2 indicates that it is in Assembled Move mode by setting input word 0 bit 8.  The driver also sets input word 0 bit 9 to tell the PLC that it is ready to recieve a assembled move segment.  When both of these bits are set, and the counter's accumulator is equal to zero, send the length, velocity, acceleration, and deceleration paramters of the first segment to the driver.
   16: XIO(Assembled_Move_counter.DN)XIC(Axis_Status_Bits.8)XIC(Axis_Status_Bits.9)EQU(Assembled_Move_counter.ACC,13)MOV(6144,command_data_block[0])CPS(Segment_14_Distance,command_data_block[2],2)CPS(Segment_14_Programmed_Speed,command_data_block[4],2)MOV(Segment_14_Acceleration,command_data_block[6])MOV(Segment_14_Deceleration,command_data_block[7]);
   // The SMD23E2 indicates that it is in Assembled Move mode by setting input word 0 bit 8.  The driver also sets input word 0 bit 9 to tell the PLC that it is ready to recieve a assembled move segment.  When both of these bits are set, and the counter's accumulator is equal to zero, send the length, velocity, acceleration, and deceleration paramters of the first segment to the driver.
   17: XIO(Assembled_Move_counter.DN)XIC(Axis_Status_Bits.8)XIC(Axis_Status_Bits.9)EQU(Assembled_Move_counter.ACC,14)MOV(6144,command_data_block[0])CPS(Segment_15_Distance,command_data_block[2],2)CPS(Segment_15_Programmed_Speed,command_data_block[4],2)MOV(Segment_15_Acceleration,command_data_block[6])MOV(Segment_15_Deceleration,command_data_block[7]);
(* Logix 5000 project; controller SMD23E2_EDS_AOI_CompactLogix_RSLogix_V28 vendor 1 type 14 code 108 rev 28.11; software revision 28.00; part 3 of 4 *)
(* tags used below, declared in another part *)
   Segment_16_Distance : DINT;
   Segment_16_Programmed_Speed : DINT;
   Segment_16_Acceleration : INT;
   Segment_16_Deceleration : INT;
   Assembled_Move_Programmed : BOOL;
   Assembled_Move_counter : COUNTER;
(* AMCI_SMD23E2_Program_Assembed_Move, continued *)

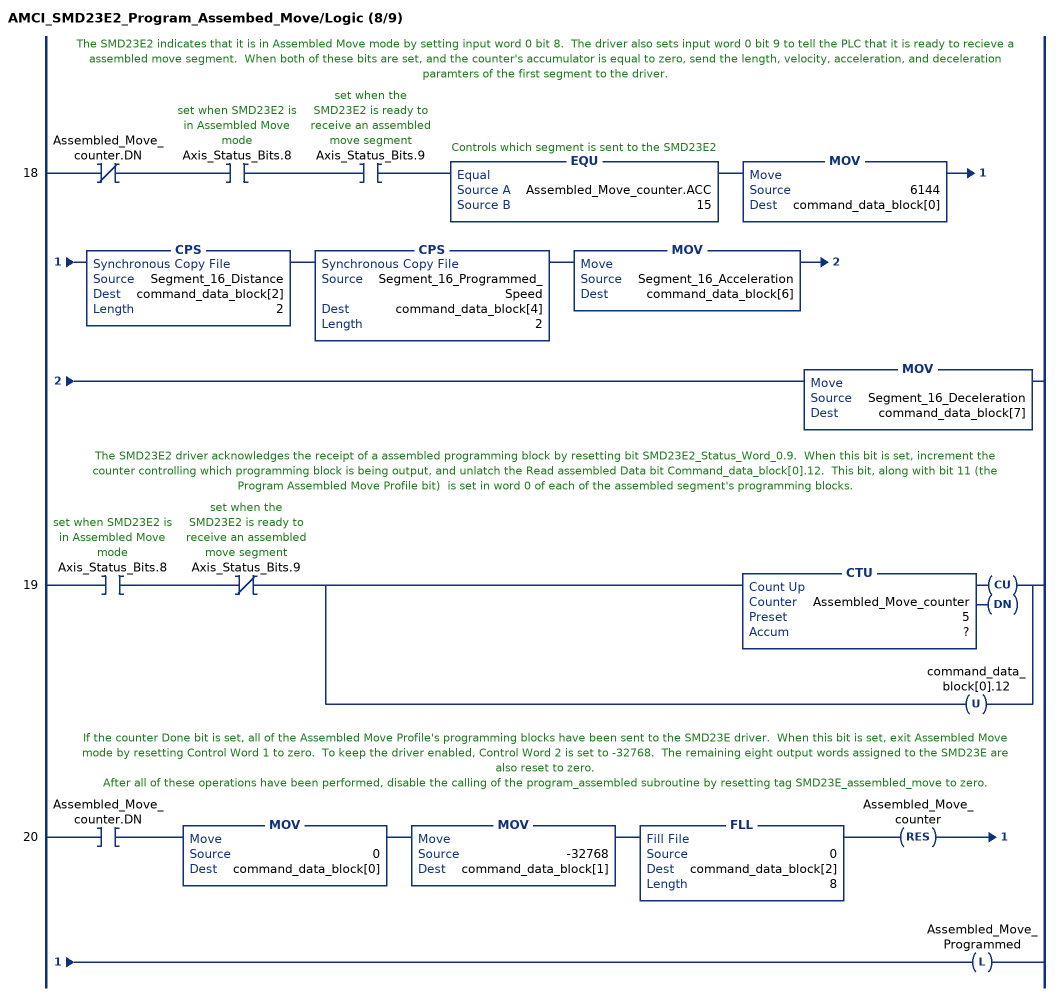
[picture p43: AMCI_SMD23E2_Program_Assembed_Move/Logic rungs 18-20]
   // The SMD23E2 indicates that it is in Assembled Move mode by setting input word 0 bit 8.  The driver also sets input word 0 bit 9 to tell the PLC that it is ready to recieve a assembled move segment.  When both of these bits are set, and the counter's accumulator is equal to zero, send the length, velocity, acceleration, and deceleration paramters of the first segment to the driver.
   18: XIO(Assembled_Move_counter.DN)XIC(Axis_Status_Bits.8)XIC(Axis_Status_Bits.9)EQU(Assembled_Move_counter.ACC,15)MOV(6144,command_data_block[0])CPS(Segment_16_Distance,command_data_block[2],2)CPS(Segment_16_Programmed_Speed,command_data_block[4],2)MOV(Segment_16_Acceleration,command_data_block[6])MOV(Segment_16_Deceleration,command_data_block[7]);
   // The SMD23E2 driver acknowledges the receipt of a assembled programming block by resetting bit SMD23E2_Status_Word_0.9.  When this bit is set, increment the counter controlling which programming block is being output, and unlatch the Read assembled Data bit Command_data_block[0].12.  This bit, along with bit 11 (the Program Assembled Move Profile bit)  is set in word 0 of each of the assembled segment's programming blocks.
   19: XIC(Axis_Status_Bits.8)XIO(Axis_Status_Bits.9)[CTU(Assembled_Move_counter,?,?) ,OTU(command_data_block[0].12) ];
   // If the counter Done bit is set, all of the Assembled Move Profile's programming blocks have been sent to the SMD23E driver.  When this bit is set, exit Assembled Move mode by resetting Control Word 1 to zero.  To keep the driver enabled, Control Word 2 is set to -32768.  The remaining eight output words assigned to the SMD23E are also reset to zero.
   // After all of these operations have been performed, disable the calling of the program_assembled subroutine by resetting tag SMD23E_assembled_move to zero.
   20: XIC(Assembled_Move_counter.DN)MOV(0,command_data_block[0])MOV(-32768,command_data_block[1])FLL(0,command_data_block[2],8)RES(Assembled_Move_counter)OTL(Assembled_Move_Programmed);
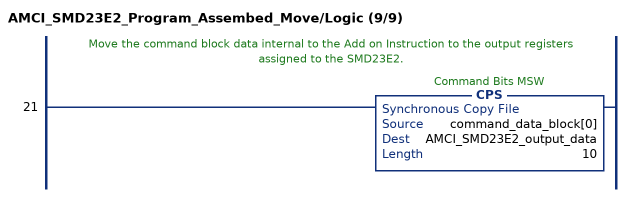
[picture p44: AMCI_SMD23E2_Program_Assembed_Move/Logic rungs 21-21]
   // Move the command block data internal to the Add on Instruction to the output registers assigned to the SMD23E2.
   21: CPS(command_data_block[0],AMCI_SMD23E2_output_data,10);
END_ROUTINE
END_ADD_ON_INSTRUCTION

ADD_ON_INSTRUCTION AMCI_SMD23E2_Program_Motor_Current   (* revision 1.0, vendor AMCI *)
VAR_INPUT
   Motor_Current : INT; {required}
END_VAR
VAR_IN_OUT
   AMCI_SMD23E2_output_data : _000A:SMD23E2_788832CB:O:0; {required}
END_VAR
VAR
   Upper_Result_X_1000 : DINT;
   command_data_block : INT[10];
        [1]   // Command Bits LSW
        [3]   // Lower Target Position
        [5]   // Lower Programmed Speed
        [0]   // Command Bits MSW
        [2]   // Upper Target Position
        [4]   // Upper Programmed Speed
END_VAR

ROUTINE Logic   (* ladder *)
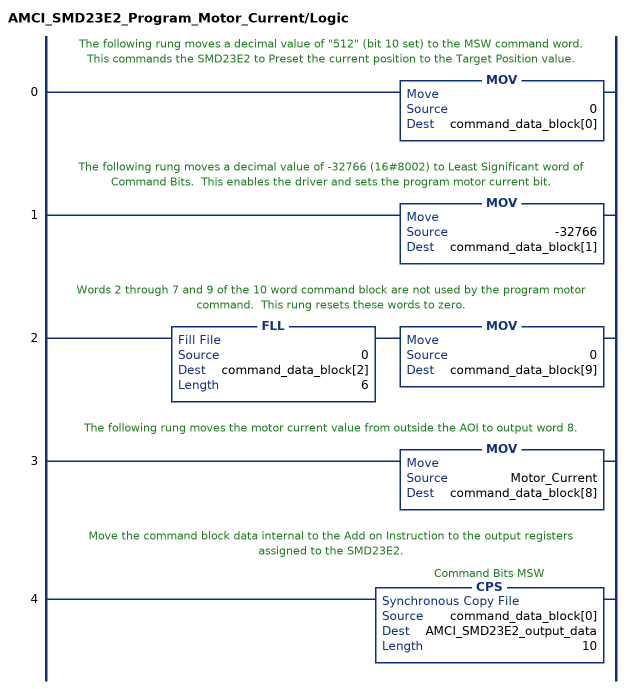
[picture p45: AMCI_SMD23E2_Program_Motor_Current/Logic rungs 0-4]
   // The following rung moves a decimal value of "512" (bit 10 set) to the MSW command word.  This commands the SMD23E2 to Preset the current position to the Target Position value.
   0: MOV(0,command_data_block[0]);
   // The following rung moves a decimal value of -32766 (16#8002) to Least Significant word of Command Bits.  This enables the driver and sets the program motor current bit.
   1: MOV(-32766,command_data_block[1]);
   // Words 2 through 7 and 9 of the 10 word command block are not used by the program motor command.  This rung resets these words to zero.
   2: FLL(0,command_data_block[2],6)MOV(0,command_data_block[9]);
   // The following rung moves the motor current value from outside the AOI to output word 8.
   3: MOV(Motor_Current,command_data_block[8]);
   // Move the command block data internal to the Add on Instruction to the output registers assigned to the SMD23E2.
   4: CPS(command_data_block[0],AMCI_SMD23E2_output_data,10);
END_ROUTINE
END_ADD_ON_INSTRUCTION

ADD_ON_INSTRUCTION AMCI_SMD23E2_Registration_Move_CCW   (* revision 5.0, vendor AMCI, ExecuteEnableInFalse *)
// Revision note:
// Version 5.0  unlatches the error bit if the rung goes false.
VAR_INPUT
   Axis_Status_Bits : INT; {required}
   Type_0_for_standard_1_for_indexed : BOOL;
   Stopping_Distance : DINT; {required}
   Programmed_Speed : DINT; {required}
   Acceleration : INT; {required}
   Deceleration : INT; {required}
   Minimum_Registration_Move_Distance : DINT; {required}
END_VAR
VAR_OUTPUT
   EN : BOOL; {access Read Only, visible}
   Registration_Move_CCW_Occurring : BOOL; {access Read Only, visible}
END_VAR
VAR_IN_OUT
   AMCI_SMD23E2_output_data : _000A:SMD23E2_788832CB:O:0; {required}
END_VAR
VAR_OUTPUT
   ER : BOOL; {access Read Only, visible}
END_VAR
VAR
   Upper_Result_X_1000 : DINT;
   command_data_block : INT[10];
        [1]   // Command Bits LSW
        [3]   // Lower Target Position
        [5]   // Lower Programmed Speed
        [0]   // Command Bits MSW
        [2]   // Upper Target Position
        [4]   // Upper Programmed Speed
END_VAR

ROUTINE EnableInFalse   (* ladder *)
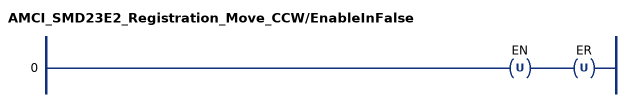
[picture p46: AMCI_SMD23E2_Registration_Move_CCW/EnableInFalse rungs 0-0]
   0: OTU(EN)OTU(ER);
END_ROUTINE

ROUTINE Logic   (* ladder *)
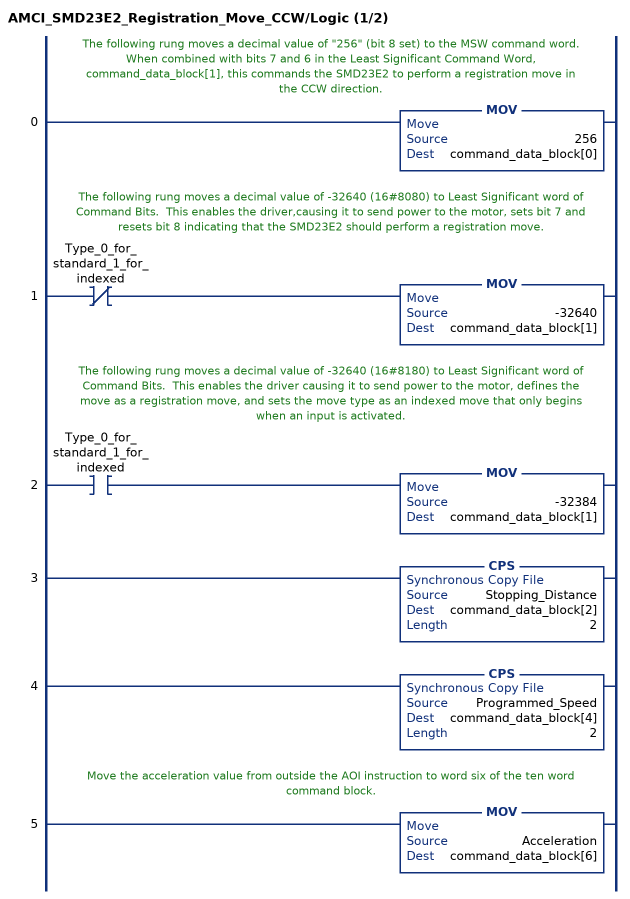
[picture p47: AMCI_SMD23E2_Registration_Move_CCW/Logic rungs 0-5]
   // The following rung moves a decimal value of "256" (bit 8 set) to the MSW command word.  When combined with bits 7 and 6 in the Least Significant Command Word, command_data_block[1], this commands the SMD23E2 to perform a registration move in the CCW direction.
   0: MOV(256,command_data_block[0]);
   // The following rung moves a decimal value of -32640 (16#8080) to Least Significant word of Command Bits.  This enables the driver,causing it to send power to the motor, sets bit 7 and resets bit 8 indicating that the SMD23E2 should perform a registration move.
   1: XIO(Type_0_for_standard_1_for_indexed)MOV(-32640,command_data_block[1]);
   // The following rung moves a decimal value of -32640 (16#8180) to Least Significant word of Command Bits.  This enables the driver causing it to send power to the motor, defines the move as a registration move, and sets the move type as an indexed move that only begins when an input is activated.
   2: XIC(Type_0_for_standard_1_for_indexed)MOV(-32384,command_data_block[1]);
   3: CPS(Stopping_Distance,command_data_block[2],2);
   4: CPS(Programmed_Speed,command_data_block[4],2);
   // Move the acceleration value from outside the AOI instruction to word six of the ten word command block.
   5: MOV(Acceleration,command_data_block[6]);
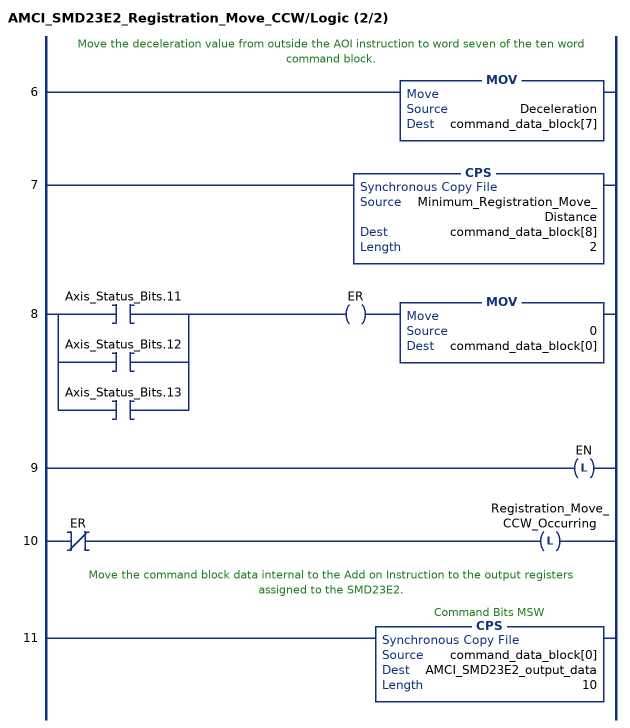
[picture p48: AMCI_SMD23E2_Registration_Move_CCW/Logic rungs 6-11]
   // Move the deceleration value from outside the AOI instruction to word seven of the ten word command block.
   6: MOV(Deceleration,command_data_block[7]);
   7: CPS(Minimum_Registration_Move_Distance,command_data_block[8],2);
   8: [XIC(Axis_Status_Bits.11) ,XIC(Axis_Status_Bits.12) ,XIC(Axis_Status_Bits.13) ]OTE(ER)MOV(0,command_data_block[0]);
   9: OTL(EN);
   10: XIO(ER)OTL(Registration_Move_CCW_Occurring);
   // Move the command block data internal to the Add on Instruction to the output registers assigned to the SMD23E2.
   11: CPS(command_data_block[0],AMCI_SMD23E2_output_data,10);
END_ROUTINE
END_ADD_ON_INSTRUCTION

ADD_ON_INSTRUCTION AMCI_SMD23E2_Registration_Move_CW   (* revision 5.0, vendor AMCI, ExecuteEnableInFalse *)
// Revision note:
// Version 5.0 a unlatches the error bit if the rung goes false.
VAR_INPUT
   Axis_Status_Bits : INT; {required}
   Type_0_for_standard_1_for_indexed : BOOL;
   Stopping_Distance : DINT; {required}
   Programmed_Speed : DINT; {required}
   Acceleration : INT; {required}
   Deceleration : INT; {required}
   Minimum_Registration_Move_Distance : DINT; {required}
END_VAR
VAR_OUTPUT
   EN : BOOL; {access Read Only, visible}
   Registration_Move_CW_Occurring : BOOL; {access Read Only, visible}
END_VAR
VAR_IN_OUT
   AMCI_SMD23E2_output_data : _000A:SMD23E2_788832CB:O:0; {required}
END_VAR
VAR_OUTPUT
   ER : BOOL; {access Read Only, visible}
END_VAR
VAR
   Upper_Result_X_1000 : DINT;
   command_data_block : INT[10];
        [1]   // Command Bits LSW
        [3]   // Lower Target Position
        [5]   // Lower Programmed Speed
        [0]   // Command Bits MSW
        [2]   // Upper Target Position
        [4]   // Upper Programmed Speed
END_VAR

ROUTINE EnableInFalse   (* ladder *)
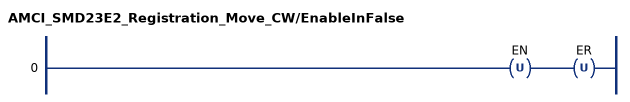
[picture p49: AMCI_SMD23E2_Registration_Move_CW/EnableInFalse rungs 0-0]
   0: OTU(EN)OTU(ER);
END_ROUTINE

ROUTINE Logic   (* ladder *)
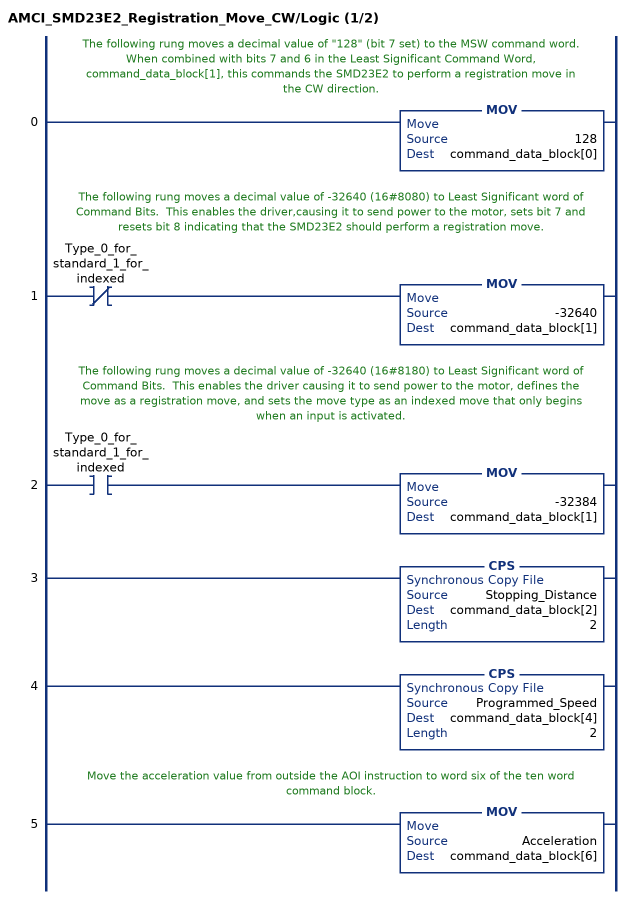
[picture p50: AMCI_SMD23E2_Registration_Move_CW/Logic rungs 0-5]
   // The following rung moves a decimal value of "128" (bit 7 set) to the MSW command word.  When combined with bits 7 and 6 in the Least Significant Command Word, command_data_block[1], this commands the SMD23E2 to perform a registration move in the CW direction.
   0: MOV(128,command_data_block[0]);
   // The following rung moves a decimal value of -32640 (16#8080) to Least Significant word of Command Bits.  This enables the driver,causing it to send power to the motor, sets bit 7 and resets bit 8 indicating that the SMD23E2 should perform a registration move.
   1: XIO(Type_0_for_standard_1_for_indexed)MOV(-32640,command_data_block[1]);
   // The following rung moves a decimal value of -32640 (16#8180) to Least Significant word of Command Bits.  This enables the driver causing it to send power to the motor, defines the move as a registration move, and sets the move type as an indexed move that only begins when an input is activated.
   2: XIC(Type_0_for_standard_1_for_indexed)MOV(-32384,command_data_block[1]);
   3: CPS(Stopping_Distance,command_data_block[2],2);
   4: CPS(Programmed_Speed,command_data_block[4],2);
   // Move the acceleration value from outside the AOI instruction to word six of the ten word command block.
   5: MOV(Acceleration,command_data_block[6]);
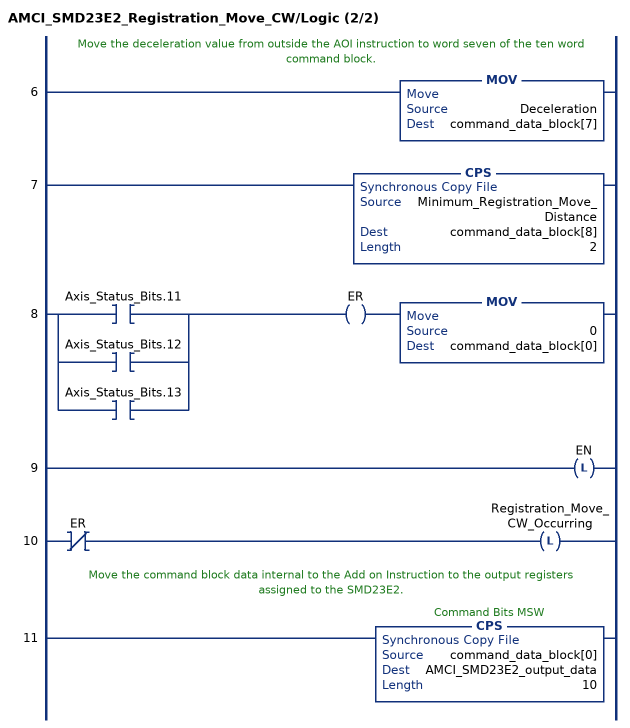
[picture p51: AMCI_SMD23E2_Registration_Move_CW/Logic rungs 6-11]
   // Move the deceleration value from outside the AOI instruction to word seven of the ten word command block.
   6: MOV(Deceleration,command_data_block[7]);
   7: CPS(Minimum_Registration_Move_Distance,command_data_block[8],2);
   8: [XIC(Axis_Status_Bits.11) ,XIC(Axis_Status_Bits.12) ,XIC(Axis_Status_Bits.13) ]OTE(ER)MOV(0,command_data_block[0]);
   9: OTL(EN);
   10: XIO(ER)OTL(Registration_Move_CW_Occurring);
   // Move the command block data internal to the Add on Instruction to the output registers assigned to the SMD23E2.
   11: CPS(command_data_block[0],AMCI_SMD23E2_output_data,10);
END_ROUTINE
END_ADD_ON_INSTRUCTION

ADD_ON_INSTRUCTION AMCI_SMD23E2_Relative_Move   (* revision 5.0, vendor AMCI, ExecuteEnableInFalse *)
// Revision note:
// Version 5.0 added the (hidden) ability to program the motor current and unlatched the error bit if the rung goes false.
VAR_INPUT
   Axis_Status_Bits : INT; {required}
   Type_0_for_standard_1_for_indexed : BOOL;
   Target_Position : DINT; {required}
   Programmed_Speed : DINT; {required}
   Acceleration : INT; {required}
   Deceleration : INT; {required}
   motor_current : INT;
   Jerk : INT;
END_VAR
VAR_IN_OUT
   AMCI_SMD23E2_output_data : _000A:SMD23E2_788832CB:O:0; {required}
END_VAR
VAR_OUTPUT
   EN : BOOL; {visible}
   ER : BOOL; {visible}
END_VAR
VAR
   Upper_Result_X_1000 : DINT;
   command_data_block : INT[10];
        [1]   // Command Bits LSW
        [3]   // Lower Target Position
        [5]   // Lower Programmed Speed
        [0]   // Command Bits MSW
        [2]   // Upper Target Position
        [4]   // Upper Programmed Speed
END_VAR

ROUTINE EnableInFalse   (* ladder *)
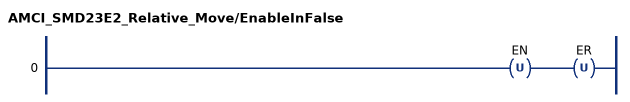
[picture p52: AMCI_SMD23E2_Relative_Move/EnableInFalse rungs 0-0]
   0: OTU(EN)OTU(ER);
END_ROUTINE

ROUTINE Logic   (* ladder *)
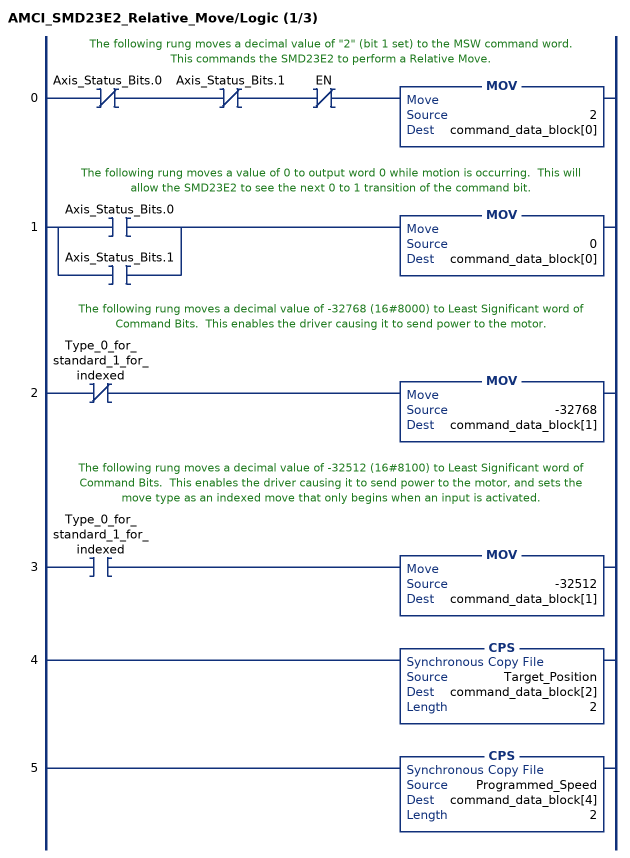
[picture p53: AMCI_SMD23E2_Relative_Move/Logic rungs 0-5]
   // The following rung moves a decimal value of "2" (bit 1 set) to the MSW command word.  This commands the SMD23E2 to perform a Relative Move.
   0: XIO(Axis_Status_Bits.0)XIO(Axis_Status_Bits.1)XIO(EN)MOV(2,command_data_block[0]);
   // The following rung moves a value of 0 to output word 0 while motion is occurring.  This will allow the SMD23E2 to see the next 0 to 1 transition of the command bit.
   1: [XIC(Axis_Status_Bits.0) ,XIC(Axis_Status_Bits.1) ]MOV(0,command_data_block[0]);
   // The following rung moves a decimal value of -32768 (16#8000) to Least Significant word of Command Bits.  This enables the driver causing it to send power to the motor.
   2: XIO(Type_0_for_standard_1_for_indexed)MOV(-32768,command_data_block[1]);
   // The following rung moves a decimal value of -32512 (16#8100) to Least Significant word of Command Bits.  This enables the driver causing it to send power to the motor, and sets the move type as an indexed move that only begins when an input is activated.
   3: XIC(Type_0_for_standard_1_for_indexed)MOV(-32512,command_data_block[1]);
   4: CPS(Target_Position,command_data_block[2],2);
   5: CPS(Programmed_Speed,command_data_block[4],2);
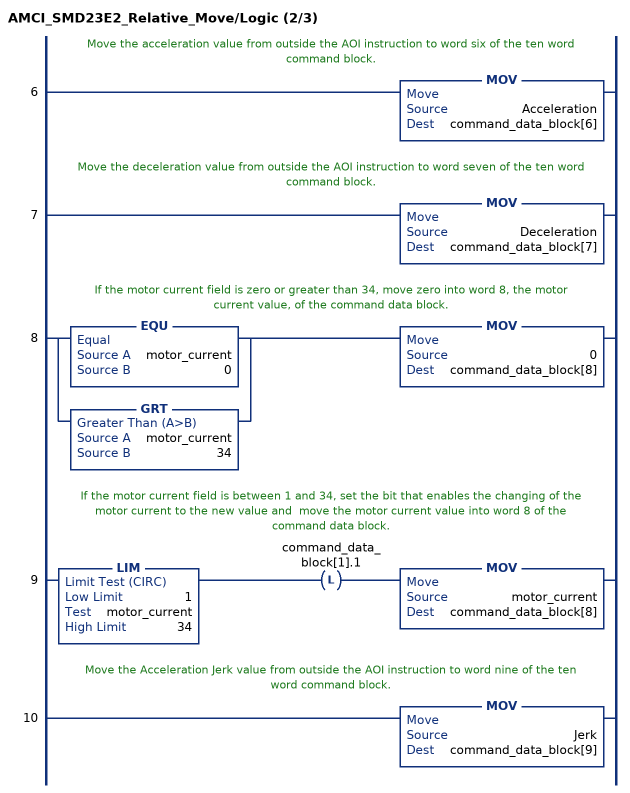
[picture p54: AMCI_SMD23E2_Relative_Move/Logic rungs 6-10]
   // Move the acceleration value from outside the AOI instruction to word six of the ten word command block.
   6: MOV(Acceleration,command_data_block[6]);
   // Move the deceleration value from outside the AOI instruction to word seven of the ten word command block.
   7: MOV(Deceleration,command_data_block[7]);
   // If the motor current field is zero or greater than 34, move zero into word 8, the motor current value, of the command data block.
   8: [EQU(motor_current,0) ,GRT(motor_current,34) ]MOV(0,command_data_block[8]);
   // If the motor current field is between 1 and 34, set the bit that enables the changing of the motor current to the new value and  move the motor current value into word 8 of the command data block.
   9: LIM(1,motor_current,34)OTL(command_data_block[1].1)MOV(motor_current,command_data_block[8]);
   // Move the Acceleration Jerk value from outside the AOI instruction to word nine of the ten word command block.
   10: MOV(Jerk,command_data_block[9]);
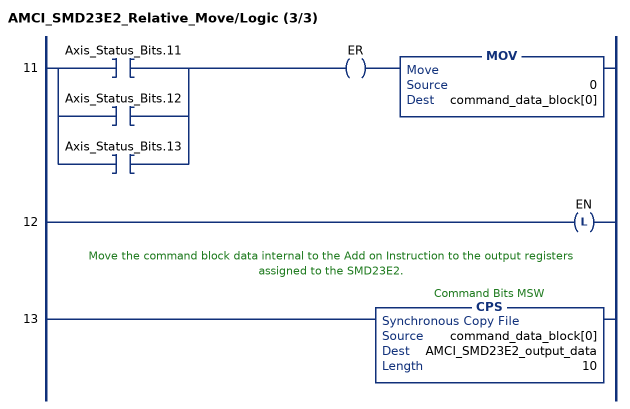
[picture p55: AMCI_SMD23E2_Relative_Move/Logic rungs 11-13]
   11: [XIC(Axis_Status_Bits.11) ,XIC(Axis_Status_Bits.12) ,XIC(Axis_Status_Bits.13) ]OTE(ER)MOV(0,command_data_block[0]);
   12: OTL(EN);
   // Move the command block data internal to the Add on Instruction to the output registers assigned to the SMD23E2.
   13: CPS(command_data_block[0],AMCI_SMD23E2_output_data,10);
END_ROUTINE
END_ADD_ON_INSTRUCTION

ADD_ON_INSTRUCTION AMCI_SMD23E2_Reset_Errors   (* revision 1.0, vendor AMCI *)
VAR_IN_OUT
   AMCI_SMD23E2_output_data : _000A:SMD23E2_788832CB:O:0; {required}
END_VAR
VAR
   command_data_block : INT[10];
        [1]   // Command Bits LSW
        [3]   // Lower Target Position
        [5]   // Lower Programmed Speed
        [0]   // Command Bits MSW
        [2]   // Upper Target Position
        [4]   // Upper Programmed Speed
END_VAR

ROUTINE Logic   (* ladder *)
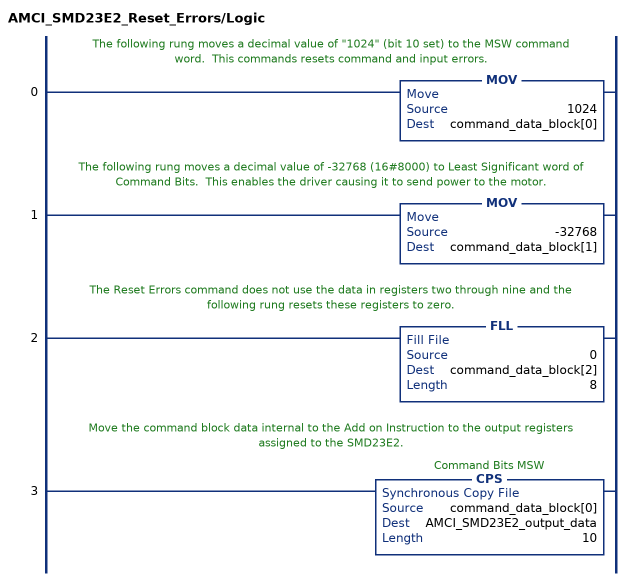
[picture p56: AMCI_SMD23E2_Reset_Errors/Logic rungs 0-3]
   // The following rung moves a decimal value of "1024" (bit 10 set) to the MSW command word.  This commands resets command and input errors.
   0: MOV(1024,command_data_block[0]);
   // The following rung moves a decimal value of -32768 (16#8000) to Least Significant word of Command Bits.  This enables the driver causing it to send power to the motor.
   1: MOV(-32768,command_data_block[1]);
   // The Reset Errors command does not use the data in registers two through nine and the following rung resets these registers to zero.
   2: FLL(0,command_data_block[2],8);
   // Move the command block data internal to the Add on Instruction to the output registers assigned to the SMD23E2.
   3: CPS(command_data_block[0],AMCI_SMD23E2_output_data,10);
END_ROUTINE
END_ADD_ON_INSTRUCTION

ADD_ON_INSTRUCTION AMCI_SMD23E2_Resume   (* revision 1.0, vendor AMCI *)
VAR_IN_OUT
   AMCI_SMD23E2_output_data : _000A:SMD23E2_788832CB:O:0; {required}
END_VAR
VAR
   command_data_block : INT[10];
        [1]   // Command Bits LSW
        [3]   // Lower Target Position
        [5]   // Lower Programmed Speed
        [0]   // Command Bits MSW
        [2]   // Upper Target Position
        [4]   // Upper Programmed Speed
END_VAR

ROUTINE Logic   (* ladder *)
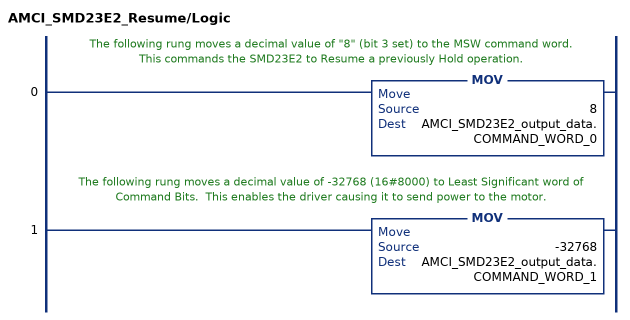
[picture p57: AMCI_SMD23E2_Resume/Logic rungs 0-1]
   // The following rung moves a decimal value of "8" (bit 3 set) to the MSW command word.  This commands the SMD23E2 to Resume a previously Hold operation.
   0: MOV(8,AMCI_SMD23E2_output_data.COMMAND_WORD_0);
   // The following rung moves a decimal value of -32768 (16#8000) to Least Significant word of Command Bits.  This enables the driver causing it to send power to the motor.
   1: MOV(-32768,AMCI_SMD23E2_output_data.COMMAND_WORD_1);
END_ROUTINE
END_ADD_ON_INSTRUCTION

ADD_ON_INSTRUCTION AMCI_SMD23E2_Run_Blend_Move   (* revision 5.0, vendor AMCI, ExecuteEnableInFalse *)
// Revision note:
// Version 5.0 added the (hidden) ability to program the motor current and unlatched the error bit if the rung goes false.
VAR_INPUT
   Axis_Status_Bits : INT; {required}
   Type_0_for_standard_1_for_indexed : BOOL;
   Direction_0_for_CW_1_for_CCW : BOOL; {required}
   motor_current : INT;
END_VAR
VAR_IN_OUT
   AMCI_SMD23E2_output_data : _000A:SMD23E2_788832CB:O:0; {required}
END_VAR
VAR_OUTPUT
   EN : BOOL; {access Read Only, visible}
   ER : BOOL; {access Read Only, visible}
END_VAR
VAR
   command_data_block : INT[10];
        [1]   // Command Bits LSW
        [3]   // Lower Target Position
        [5]   // Lower Programmed Speed
        [0]   // Command Bits MSW
        [2]   // Upper Target Position
        [4]   // Upper Programmed Speed
END_VAR

ROUTINE EnableInFalse   (* ladder *)
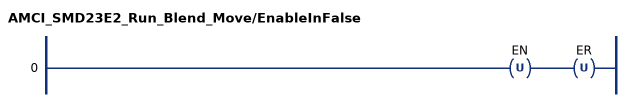
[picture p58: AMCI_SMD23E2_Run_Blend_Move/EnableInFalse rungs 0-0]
   0: OTU(EN)OTU(ER);
END_ROUTINE

ROUTINE Logic   (* ladder *)
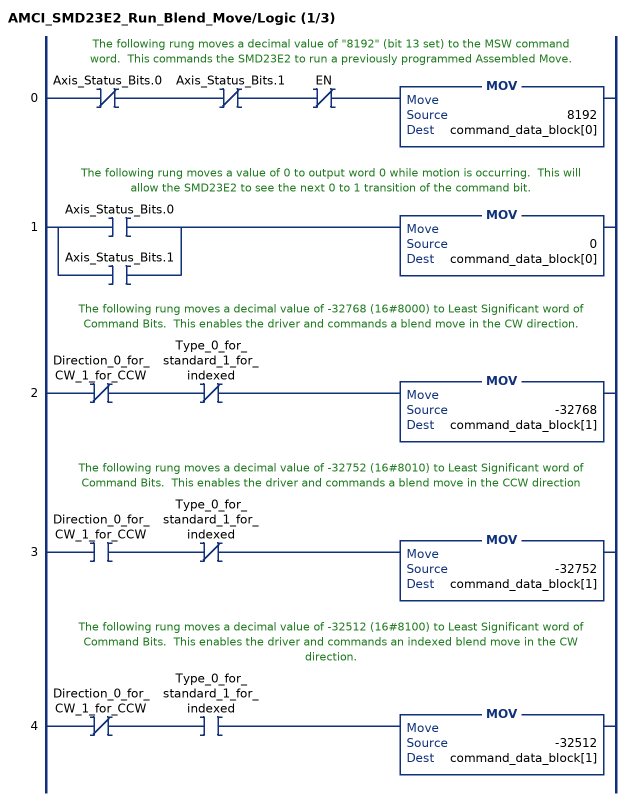
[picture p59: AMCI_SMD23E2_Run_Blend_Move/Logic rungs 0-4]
   // The following rung moves a decimal value of "8192" (bit 13 set) to the MSW command word.  This commands the SMD23E2 to run a previously programmed Assembled Move.
   0: XIO(Axis_Status_Bits.0)XIO(Axis_Status_Bits.1)XIO(EN)MOV(8192,command_data_block[0]);
   // The following rung moves a value of 0 to output word 0 while motion is occurring.  This will allow the SMD23E2 to see the next 0 to 1 transition of the command bit.
   1: [XIC(Axis_Status_Bits.0) ,XIC(Axis_Status_Bits.1) ]MOV(0,command_data_block[0]);
   // The following rung moves a decimal value of -32768 (16#8000) to Least Significant word of Command Bits.  This enables the driver and commands a blend move in the CW direction.
   2: XIO(Direction_0_for_CW_1_for_CCW)XIO(Type_0_for_standard_1_for_indexed)MOV(-32768,command_data_block[1]);
   // The following rung moves a decimal value of -32752 (16#8010) to Least Significant word of Command Bits.  This enables the driver and commands a blend move in the CCW direction
   3: XIC(Direction_0_for_CW_1_for_CCW)XIO(Type_0_for_standard_1_for_indexed)MOV(-32752,command_data_block[1]);
   // The following rung moves a decimal value of -32512 (16#8100) to Least Significant word of Command Bits.  This enables the driver and commands an indexed blend move in the CW direction.
   4: XIO(Direction_0_for_CW_1_for_CCW)XIC(Type_0_for_standard_1_for_indexed)MOV(-32512,command_data_block[1]);
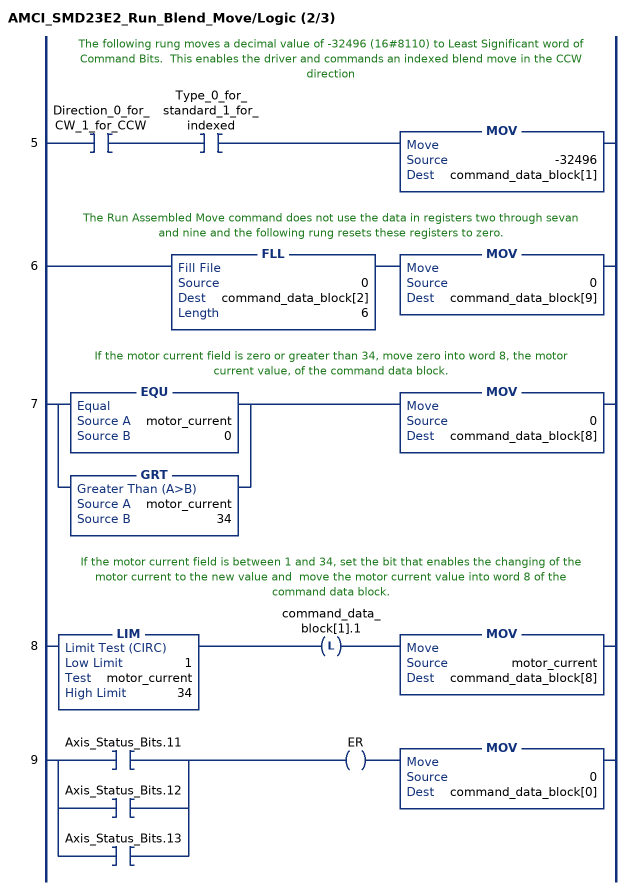
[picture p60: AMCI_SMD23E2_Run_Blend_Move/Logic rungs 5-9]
   // The following rung moves a decimal value of -32496 (16#8110) to Least Significant word of Command Bits.  This enables the driver and commands an indexed blend move in the CCW direction
   5: XIC(Direction_0_for_CW_1_for_CCW)XIC(Type_0_for_standard_1_for_indexed)MOV(-32496,command_data_block[1]);
   // The Run Assembled Move command does not use the data in registers two through sevan and nine and the following rung resets these registers to zero.
   6: FLL(0,command_data_block[2],6)MOV(0,command_data_block[9]);
   // If the motor current field is zero or greater than 34, move zero into word 8, the motor current value, of the command data block.
   7: [EQU(motor_current,0) ,GRT(motor_current,34) ]MOV(0,command_data_block[8]);
   // If the motor current field is between 1 and 34, set the bit that enables the changing of the motor current to the new value and  move the motor current value into word 8 of the command data block.
   8: LIM(1,motor_current,34)OTL(command_data_block[1].1)MOV(motor_current,command_data_block[8]);
   9: [XIC(Axis_Status_Bits.11) ,XIC(Axis_Status_Bits.12) ,XIC(Axis_Status_Bits.13) ]OTE(ER)MOV(0,command_data_block[0]);
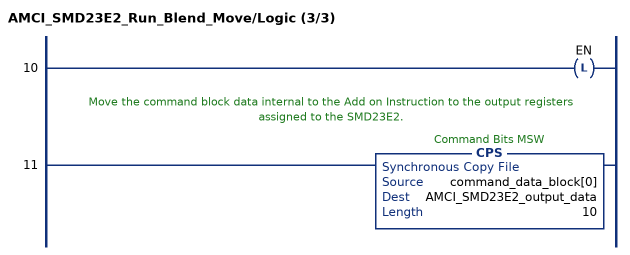
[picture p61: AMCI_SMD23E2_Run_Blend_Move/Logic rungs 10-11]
   10: OTL(EN);
   // Move the command block data internal to the Add on Instruction to the output registers assigned to the SMD23E2.
   11: CPS(command_data_block[0],AMCI_SMD23E2_output_data,10);
END_ROUTINE
END_ADD_ON_INSTRUCTION
(* Logix 5000 project; controller SMD23E2_EDS_AOI_CompactLogix_RSLogix_V28 vendor 1 type 14 code 108 rev 28.11; software revision 28.00; part 4 of 4 *)

ADD_ON_INSTRUCTION AMCI_SMD23E2_Run_Dwell_Move   (* revision 5.0, vendor AMCI, ExecuteEnableInFalse *)
// Revision note:
// Version 5.0 added the (hidden) ability to program the motor current and unlatched the error bit if the rung goes false.
VAR_INPUT
   Axis_Status_Bits : INT; {required}
   Type_0_for_standard_1_for_indexed : BOOL;
   Assembled_Move_Dwell_Time : INT; {required}
   motor_current : INT;
END_VAR
VAR_IN_OUT
   AMCI_SMD23E2_output_data : _000A:SMD23E2_788832CB:O:0; {required}
END_VAR
VAR_OUTPUT
   EN : BOOL; {visible}
   ER : BOOL; {visible}
END_VAR
VAR
   command_data_block : INT[10];
        [1]   // Command Bits LSW
        [3]   // Lower Target Position
        [5]   // Lower Programmed Speed
        [0]   // Command Bits MSW
        [2]   // Upper Target Position
        [4]   // Upper Programmed Speed
END_VAR

ROUTINE EnableInFalse   (* ladder *)
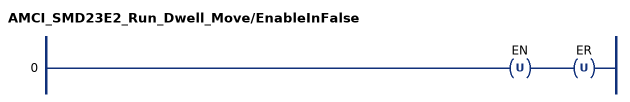
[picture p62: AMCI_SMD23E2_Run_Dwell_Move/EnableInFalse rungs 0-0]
   0: OTU(EN)OTU(ER);
END_ROUTINE

ROUTINE Logic   (* ladder *)
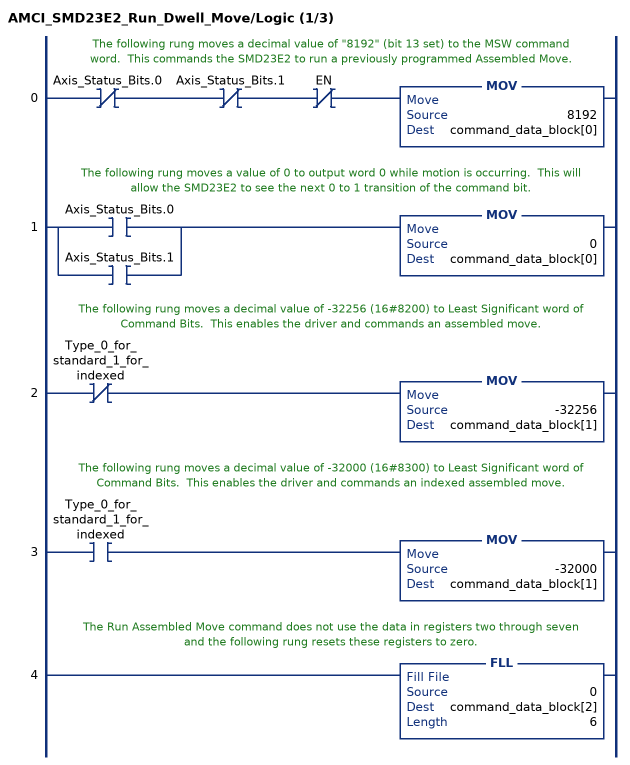
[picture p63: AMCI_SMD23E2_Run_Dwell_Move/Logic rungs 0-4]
   // The following rung moves a decimal value of "8192" (bit 13 set) to the MSW command word.  This commands the SMD23E2 to run a previously programmed Assembled Move.
   0: XIO(Axis_Status_Bits.0)XIO(Axis_Status_Bits.1)XIO(EN)MOV(8192,command_data_block[0]);
   // The following rung moves a value of 0 to output word 0 while motion is occurring.  This will allow the SMD23E2 to see the next 0 to 1 transition of the command bit.
   1: [XIC(Axis_Status_Bits.0) ,XIC(Axis_Status_Bits.1) ]MOV(0,command_data_block[0]);
   // The following rung moves a decimal value of -32256 (16#8200) to Least Significant word of Command Bits.  This enables the driver and commands an assembled move.
   2: XIO(Type_0_for_standard_1_for_indexed)MOV(-32256,command_data_block[1]);
   // The following rung moves a decimal value of -32000 (16#8300) to Least Significant word of Command Bits.  This enables the driver and commands an indexed assembled move.
   3: XIC(Type_0_for_standard_1_for_indexed)MOV(-32000,command_data_block[1]);
   // The Run Assembled Move command does not use the data in registers two through seven and the following rung resets these registers to zero.
   4: FLL(0,command_data_block[2],6);
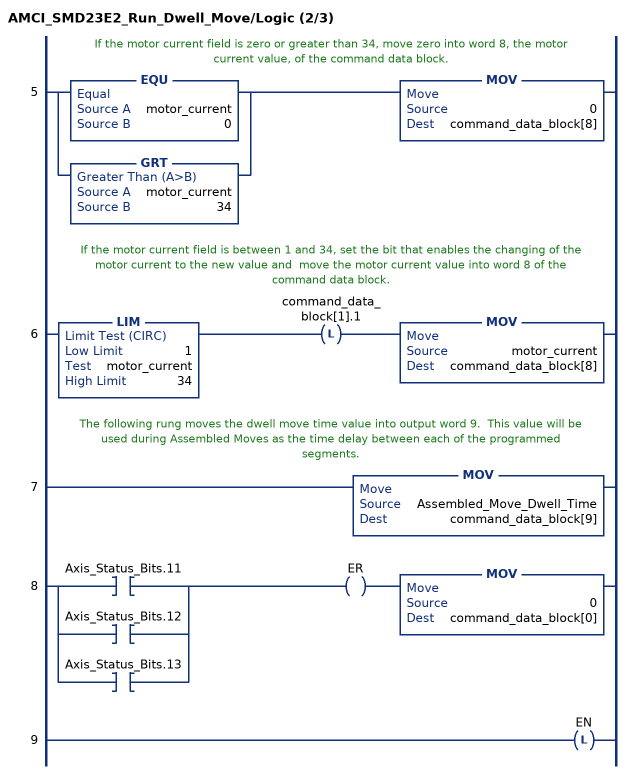
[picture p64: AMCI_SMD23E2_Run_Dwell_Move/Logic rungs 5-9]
   // If the motor current field is zero or greater than 34, move zero into word 8, the motor current value, of the command data block.
   5: [EQU(motor_current,0) ,GRT(motor_current,34) ]MOV(0,command_data_block[8]);
   // If the motor current field is between 1 and 34, set the bit that enables the changing of the motor current to the new value and  move the motor current value into word 8 of the command data block.
   6: LIM(1,motor_current,34)OTL(command_data_block[1].1)MOV(motor_current,command_data_block[8]);
   // The following rung moves the dwell move time value into output word 9.  This value will be used during Assembled Moves as the time delay between each of the programmed segments.
   7: MOV(Assembled_Move_Dwell_Time,command_data_block[9]);
   8: [XIC(Axis_Status_Bits.11) ,XIC(Axis_Status_Bits.12) ,XIC(Axis_Status_Bits.13) ]OTE(ER)MOV(0,command_data_block[0]);
   9: OTL(EN);
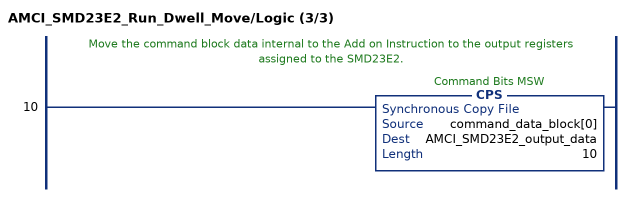
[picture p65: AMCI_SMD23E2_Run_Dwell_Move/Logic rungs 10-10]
   // Move the command block data internal to the Add on Instruction to the output registers assigned to the SMD23E2.
   10: CPS(command_data_block[0],AMCI_SMD23E2_output_data,10);
END_ROUTINE
END_ADD_ON_INSTRUCTION

VAR_GLOBAL   (* controller tags *)
   AMCI_Sample_Master : AXIS_VIRTUAL;
   AMCI_sample_motion_group : MOTION_GROUP;
   buffered_SMD23E2_data : INT[10];
        [0].0   // AMCI SMD23E2 motion occuring CW
        [0].1   // AMCI SMD23E2 motion occuring CCW
        [0].7   // SMD23E2 Move Compete bit
        [0].8   // set when SD17060E is in blend move mode
        [0].9   // set when the SD17060E is ready to receive a blend move segment
        [1].7   // AMCI SMD23E set when driver fault
        [0].10   // AMCI SMD23E2 position invalid bit
        [0].13   // AMCI SMD23E22 configuration error
        [0].14   // AMCI SMD23E2 OK bit
        [0].15   // AMCI SMD23E2 mode bit 1=config mode 0=command mode
        [1].15   // AMCI SMD23E set when driver enabled
   CCW_jog_Acceleration : INT := 10;
   CCW_jog_Deceleration : INT := 10;
   CCW_jog_Programmed_Speed : DINT := 2500;
   comment : INT;   // used as output instruction on comment rungs
   conversion_constant_read : REAL;
   CW_Home_Acceleration : INT := 10;
   CW_Home_Deceleration : INT := 10;
   CW_Home_Programmed_Speed : DINT := 500;
   CW_jog_Acceleration : INT := 10;
   CW_jog_Deceleration : INT := 10;
   CW_jog_Programmed_Speed : DINT := 1250;
   one_shot_1 : BOOL;
   one_shot_2 : BOOL;
   one_shot_3 : BOOL;
   position_unwind_read : DINT;
   preset_SMD23E2_Target_Position : DINT;
   relative_move_acceleration : INT := 10;
   relative_move_deceleration : INT := 10;
   relative_move_programmed_speed : DINT := 2000;
   relative_move_target_position : DINT := 5000;
   run_SMD23E2 : INT;   // 1=run relative move 2=run CW Jog move 3=run CCW Jog move 4=Home CW 5=Preset Motor 6=Reset Errors 7=Programmed Assembled 8=Follower Linear 9=Follower Circular
   smd23E2_communication_status : INT;
END_VAR

PROGRAM MainProgram   (* main routine MainRoutine *)
VAR
   AOI_absolute_move : AMCI_SMD23E2_Absolute_Move;
   AOI_Axis_Follower : AMCI_SMD23E2_Axis_Follower_Linear;
   AOI_CCW_Jog_Move : AMCI_SMD23E2_Jog_CCW;
   AOI_CCW_registration : AMCI_SMD23E2_Registration_Move_CCW;
   AOI_CW_Jog_Move : AMCI_SMD23E2_Jog_CW;
   AOI_disable_driver : AMCI_SMD23E2_Disable_Driver;
   AOI_Enable_driver : AMCI_SMD23E2_Enable_Driver;
   AOI_Enable_ENET_Driver : AMCI_SMD23E2_Enable_Driver;
   AOI_Hold : AMCI_SMD23E2_Hold;
   AOI_Home_CCW : AMCI_SMD23E2_Home_CCW;
   AOI_Home_CW : AMCI_SMD23E2_Home_CW;
   AOI_Immediate_stop : AMCI_SMD23E2_Immediate_Stop;
   AOI_motor_current : AMCI_SMD23E2_Program_Motor_Current;
   AOI_preset_motor_to_encoder : AMCI_SMD23E2_Preset_Motor_to_Encoder;
   AOI_Preset_Position : AMCI_SMD23E2_Preset_Motor_Position;
   AOI_program_assembled : AMCI_SMD23E2_Program_Assembed_Move;
   AOI_Registration_CW : AMCI_SMD23E2_Registration_Move_CW;
   AOI_relative_move : AMCI_SMD23E2_Relative_Move;
   AOI_Reset_Errors : AMCI_SMD23E2_Reset_Errors;
   AOI_resume : AMCI_SMD23E2_Resume;
   AOI_run_blend : AMCI_SMD23E2_Run_Blend_Move;
   AOI_run_dwell : AMCI_SMD23E2_Run_Dwell_Move;
   Preset_encoder : AMCI_SMD23E2_Preset_Encoder_Position;
END_VAR

ROUTINE assembled_blend   (* ladder *)
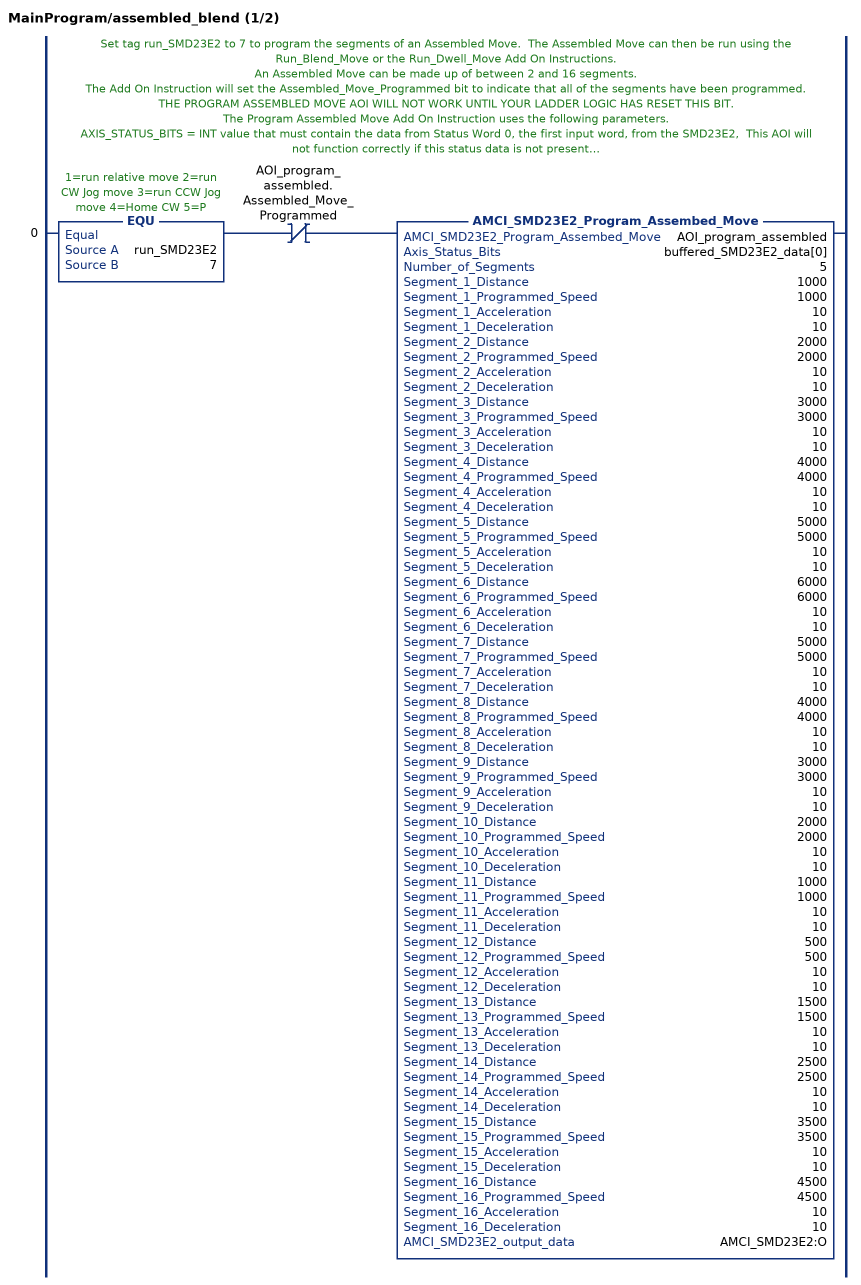
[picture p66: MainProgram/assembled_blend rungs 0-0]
   // Set tag run_SMD23E2 to 7 to program the segments of an Assembled Move.  The Assembled Move can then be run using the Run_Blend_Move or the Run_Dwell_Move Add On Instructions.
   // An Assembled Move can be made up of between 2 and 16 segments.
   // The Add On Instruction will set the Assembled_Move_Programmed bit to indicate that all of the segments have been programmed.  THE PROGRAM ASSEMBLED MOVE AOI WILL NOT WORK UNTIL YOUR LADDER LOGIC HAS RESET THIS BIT.
   // The Program Assembled Move Add On Instruction uses the following parameters.
   // AXIS_STATUS_BITS = INT value that must contain the data from Status Word 0, the first input word, from the SMD23E2,  This AOI will not function correctly if this status data is not present.
   // NUMBER OF SEGMENTS: An actual value or an INT type register that has a range of 2 to 16 and specifies the number of segments of the Assembled Move.
   // SEGMENT_X_DISTANCE: An actual value or a DINT type register.  The relative distance of each of the Assembled Move Segments.
   // SEGMENT_X_PROGRAMMED_SPEED: An actual value or a DINT type register.  The running speed of each of the programmed segments.
   // SEGMENT_X_ACCELERATION: An actual value or an INT type register that defines how fast the speed of one segment will change to the speed of another segment.
   // SEGMENT_X_Deceleration: An actual value or an INT type register that defines how fast the speed of one segment will change to the speed of another segment.
   // BOOL Assembled_MOVE_Programmed bit indicates when all of the segments have been programmed.
   // Register run_SMD23E2 is only an internal tag used to illustrate how the rung must go from false to true to make the move operation occur, and is set by either manually typing the number into the register or having your ladder logic move a value into the register.  IT IS NOT NECESSASRY TO USE THIS REGISTER OR AN EQUAL INSTRUCTION TO SEND COMMANDS TO THE AMCI SMD23E2.  You can replace it with any other condition that makes the rung true, such as a push button on a HMI terminal.
   0: EQU(run_SMD23E2,7)XIO(AOI_program_assembled.Assembled_Move_Programmed)AMCI_SMD23E2_Program_Assembed_Move(AOI_program_assembled,buffered_SMD23E2_data[0],5,1000,1000,10,10,2000,2000,10,10,3000,3000,10,10,4000,4000,10,10,5000,5000,10,10,6000,6000,10,10,5000,5000,10,10,4000,4000,10,10,3000,3000,10,10,2000,2000,10,10,1000,1000,10,10,500,500,10,10,1500,1500,10,10,2500,2500,10,10,3500,3500,10,10,4500,4500,10,10,AMCI_SMD23E2:O);
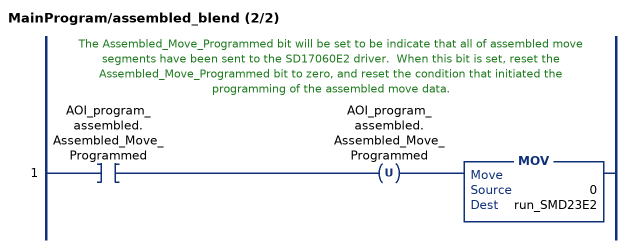
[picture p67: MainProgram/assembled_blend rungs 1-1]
   // The Assembled_Move_Programmed bit will be set to be indicate that all of assembled move segments have been sent to the SD17060E2 driver.  When this bit is set, reset the Assembled_Move_Programmed bit to zero, and reset the condition that initiated the programming of the assembled move data.
   1: XIC(AOI_program_assembled.Assembled_Move_Programmed)OTU(AOI_program_assembled.Assembled_Move_Programmed)MOV(0,run_SMD23E2);
END_ROUTINE

ROUTINE axis_follower_linear   (* ladder *)
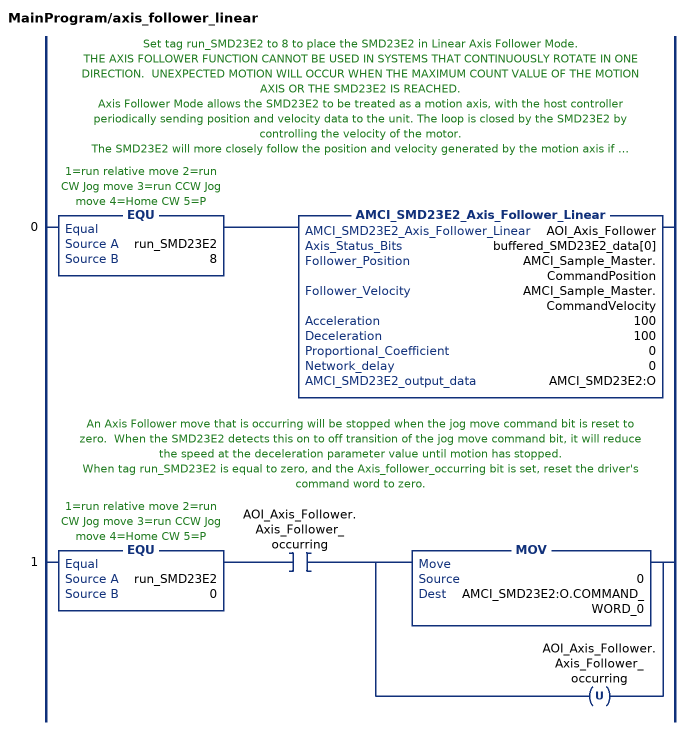
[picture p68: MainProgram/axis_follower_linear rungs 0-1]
   // Set tag run_SMD23E2 to 8 to place the SMD23E2 in Linear Axis Follower Mode.
   // THE AXIS FOLLOWER FUNCTION CANNOT BE USED IN SYSTEMS THAT CONTINUOUSLY ROTATE IN ONE DIRECTION.  UNEXPECTED MOTION WILL OCCUR WHEN THE MAXIMUM COUNT VALUE OF THE MOTION AXIS OR THE SMD23E2 IS REACHED.
   // Axis Follower Mode allows the SMD23E2 to be treated as a motion axis, with the host controller periodically sending position and velocity data to the unit. The loop is closed by the SMD23E2 by controlling the velocity of the motor.
   // The SMD23E2 will more closely follow the position and velocity generated by the motion axis if a smaller RPI time is used.  The SMD23E2’s minimum RPI time is 1.5ms and a value of 2ms is recommended.
   // The following Add On Instruction places the SMD23E2 in Axis Follower mode and sends the command data, along with the position and velocity directly from the motion axis, to the SMD23E2.  The data also includes the follower type (motor or encoder) acceleration, deceleration, a proportional coefficient parameter, and a network delay parameter.
   // Axis_Status_Bits:  This is the MSW status word from the SMD23E2, and the data contained in this register is used by the Add On Instruction to set the Motion Occurring and ER bits.
   // Follower_Position = REAL DATA TYPE position directly from the motion axis
   // Follower_Velocity = REAL DATA TYPE velocity directly from the motion axis
   // Acceleration and Deceleration = an actual value or an INT DATA TYPE register
   // Proportional coefficient = an actual value or an INT TYPE register.  A value of  0 to 2 is recommended.
   // Network Delay = an actual value or an INT TYPE register. This parameter, entered in milliseconds, can be used to compensate for network communication delays.  A value of zero will work in most applications.   If required, use values between 1 and the RPI time to smooth the motion.
   // BOOL Bit Axis_follower_occurring is a flag to indicate that an axis follower move is occurring.
   // Register run_SMD23E2 is only an internal tag used to illustrate how the rung must go from false to true to make the move operation occur, and is set by either manually typing the number into the register or having your ladder logic move a value into the register.  IT IS NOT NECESSASRY TO USE THIS REGISTER OR AN EQUAL INSTRUCTION TO SEND COMMANDS TO THE AMCI SMD23E2.  You can replace it with any other condition that makes the rung true, such as a push button on a HMI terminal.
   0: EQU(run_SMD23E2,8)AMCI_SMD23E2_Axis_Follower_Linear(AOI_Axis_Follower,buffered_SMD23E2_data[0],AMCI_Sample_Master.CommandPosition,AMCI_Sample_Master.CommandVelocity,100,100,0,0,AMCI_SMD23E2:O);
   // An Axis Follower move that is occurring will be stopped when the jog move command bit is reset to zero.  When the SMD23E2 detects this on to off transition of the jog move command bit, it will reduce the speed at the deceleration parameter value until motion has stopped.
   // When tag run_SMD23E2 is equal to zero, and the Axis_follower_occurring bit is set, reset the driver's command word to zero.
   1: EQU(run_SMD23E2,0)XIC(AOI_Axis_Follower.Axis_Follower_occurring)[MOV(0,AMCI_SMD23E2:O.COMMAND_WORD_0) ,OTU(AOI_Axis_Follower.Axis_Follower_occurring) ];
END_ROUTINE

ROUTINE MainRoutine   (* ladder *)
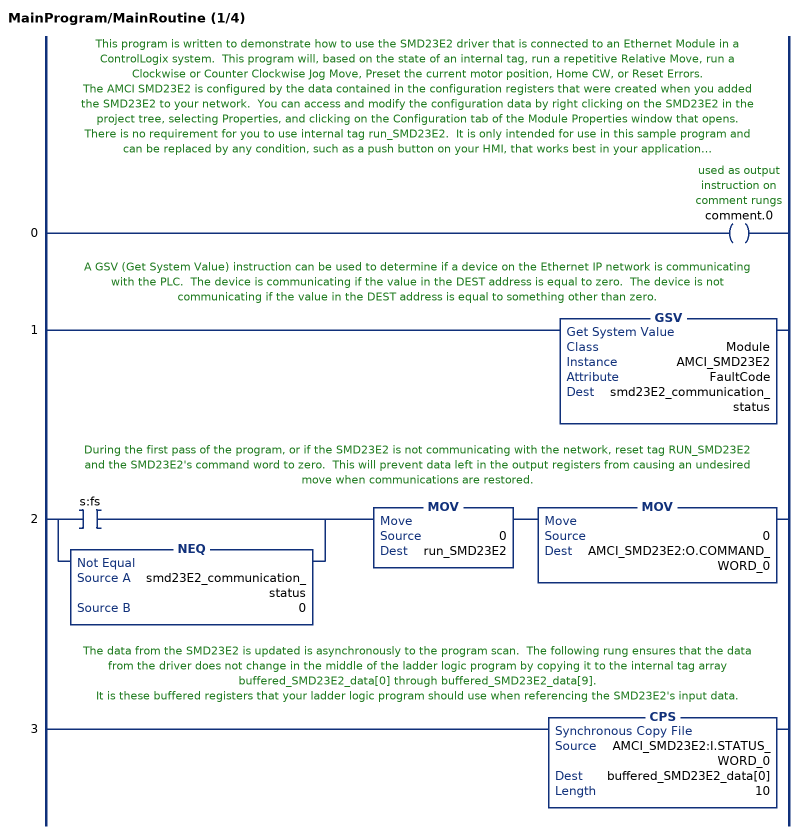
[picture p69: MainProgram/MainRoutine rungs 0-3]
   // This program is written to demonstrate how to use the SMD23E2 driver that is connected to an Ethernet Module in a ControlLogix system.  This program will, based on the state of an internal tag, run a repetitive Relative Move, run a Clockwise or Counter Clockwise Jog Move, Preset the current motor position, Home CW, or Reset Errors.
   // The AMCI SMD23E2 is configured by the data contained in the configuration registers that were created when you added the SMD23E2 to your network.  You can access and modify the configuration data by right clicking on the SMD23E2 in the project tree, selecting Properties, and clicking on the Configuration tab of the Module Properties window that opens.
   // There is no requirement for you to use internal tag run_SMD23E2.  It is only intended for use in this sample program and can be replaced by any condition, such as a push button on your HMI, that works best in your application.
   // CPS instructions are used in place of COP instructions to ensure that the transfer of data from the PLC to the SMD23E2 is not interrupted by RPI I/O update of the driver.
   // This program uses Add On Instructions for most of the SMD23E2's functions.  These instructions prompt you for what data is required for the requested move operation, set / reset the appropriate control bits and words, and enable the driver.  Although they are not shown in the program, Add On Instructions for most of the SMD23E2's functions are available in the Add-On Instructions section of the project tree.
   // Some of the Add On Instructions have some of the less commonly used functions, such as Indexed Moves or Acceleration Jerk, hidden.   The Add On Instructions are not locked or protected and, if desired, these functions can be made visible and enabled.
   // This sample program has subroutines that explain and show the use of two of the more complex Add On Instructions, Axis Follower and Program Assembled Move.  Ignore or delete these subroutines if you are not using these functions.
   // The SMD23E2 was added to the network using V1.6 of SMD23E2 EDS file.   The Add On Instructions used in this program will only function with V1.6 of the EDS file and if the input and output data formats are set to binary.
   0: OTE(comment.0);
   // A GSV (Get System Value) instruction can be used to determine if a device on the Ethernet IP network is communicating with the PLC.  The device is communicating if the value in the DEST address is equal to zero.  The device is not communicating if the value in the DEST address is equal to something other than zero.
   1: GSV(Module,AMCI_SMD23E2,FaultCode,smd23E2_communication_status);
   // During the first pass of the program, or if the SMD23E2 is not communicating with the network, reset tag RUN_SMD23E2 and the SMD23E2's command word to zero.  This will prevent data left in the output registers from causing an undesired move when communications are restored.
   2: [XIC(s:fs) ,NEQ(smd23E2_communication_status,0) ]MOV(0,run_SMD23E2)MOV(0,AMCI_SMD23E2:O.COMMAND_WORD_0);
   // The data from the SMD23E2 is updated is asynchronously to the program scan.  The following rung ensures that the data from the driver does not change in the middle of the ladder logic program by copying it to the internal tag array buffered_SMD23E2_data[0] through buffered_SMD23E2_data[9].
   // It is these buffered registers that your ladder logic program should use when referencing the SMD23E2's input data.
   3: CPS(AMCI_SMD23E2:I.STATUS_WORD_0,buffered_SMD23E2_data[0],10);
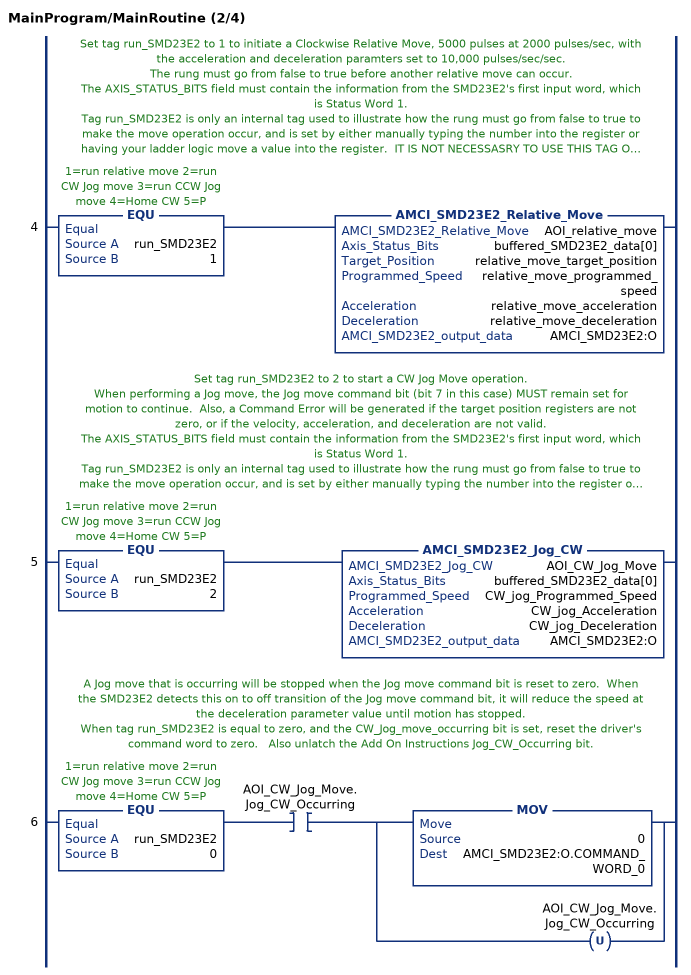
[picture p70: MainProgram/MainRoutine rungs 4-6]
   // Set tag run_SMD23E2 to 1 to initiate a Clockwise Relative Move, 5000 pulses at 2000 pulses/sec, with the acceleration and deceleration paramters set to 10,000 pulses/sec/sec.
   // The rung must go from false to true before another relative move can occur.
   // The AXIS_STATUS_BITS field must contain the information from the SMD23E2's first input word, which is Status Word 1.
   // Tag run_SMD23E2 is only an internal tag used to illustrate how the rung must go from false to true to make the move operation occur, and is set by either manually typing the number into the register or having your ladder logic move a value into the register.  IT IS NOT NECESSASRY TO USE THIS TAG OR AN EQUAL INSTRUCTION TO SEND COMMANDS TO THE AMCI SMD23E2.  You can replace it with any other condition that makes the rung true, such as a push button on a HMI terminal.
   4: EQU(run_SMD23E2,1)AMCI_SMD23E2_Relative_Move(AOI_relative_move,buffered_SMD23E2_data[0],relative_move_target_position,relative_move_programmed_speed,relative_move_acceleration,relative_move_deceleration,AMCI_SMD23E2:O);
   // Set tag run_SMD23E2 to 2 to start a CW Jog Move operation.
   // When performing a Jog move, the Jog move command bit (bit 7 in this case) MUST remain set for motion to continue.  Also, a Command Error will be generated if the target position registers are not zero, or if the velocity, acceleration, and deceleration are not valid.
   // The AXIS_STATUS_BITS field must contain the information from the SMD23E2's first input word, which is Status Word 1.
   // Tag run_SMD23E2 is only an internal tag used to illustrate how the rung must go from false to true to make the move operation occur, and is set by either manually typing the number into the register or having your ladder logic move a value into the register.  IT IS NOT NECESSASRY TO USE THIS TAG OR AN EQUAL INSTRUCTION TO SEND COMMANDS TO THE AMCI SMD23E2.  You can replace it with any other condition that makes the rung true, such as a push button on a HMI terminal.
   5: EQU(run_SMD23E2,2)AMCI_SMD23E2_Jog_CW(AOI_CW_Jog_Move,buffered_SMD23E2_data[0],CW_jog_Programmed_Speed,CW_jog_Acceleration,CW_jog_Deceleration,AMCI_SMD23E2:O);
   // A Jog move that is occurring will be stopped when the Jog move command bit is reset to zero.  When the SMD23E2 detects this on to off transition of the Jog move command bit, it will reduce the speed at the deceleration parameter value until motion has stopped.
   // When tag run_SMD23E2 is equal to zero, and the CW_Jog_move_occurring bit is set, reset the driver's command word to zero.   Also unlatch the Add On Instructions Jog_CW_Occurring bit.
   6: EQU(run_SMD23E2,0)XIC(AOI_CW_Jog_Move.Jog_CW_Occurring)[MOV(0,AMCI_SMD23E2:O.COMMAND_WORD_0) ,OTU(AOI_CW_Jog_Move.Jog_CW_Occurring) ];
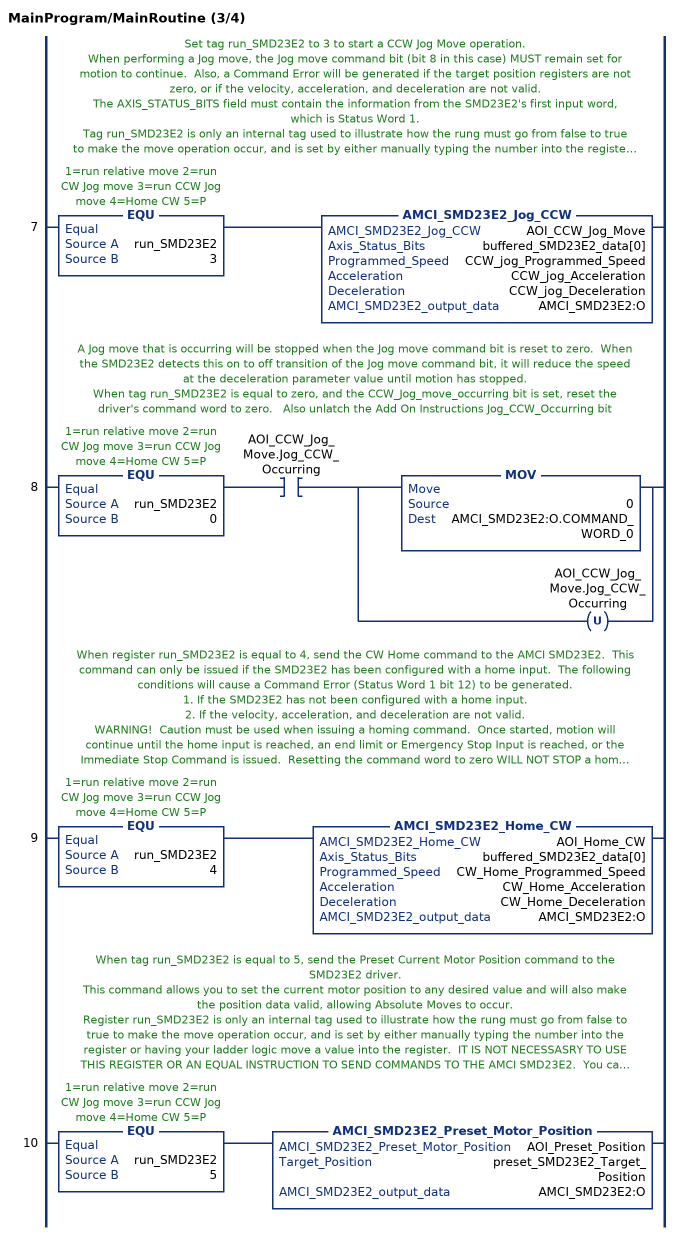
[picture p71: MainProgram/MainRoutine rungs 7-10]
   // Set tag run_SMD23E2 to 3 to start a CCW Jog Move operation.
   // When performing a Jog move, the Jog move command bit (bit 8 in this case) MUST remain set for motion to continue.  Also, a Command Error will be generated if the target position registers are not zero, or if the velocity, acceleration, and deceleration are not valid.
   // The AXIS_STATUS_BITS field must contain the information from the SMD23E2's first input word, which is Status Word 1.
   // Tag run_SMD23E2 is only an internal tag used to illustrate how the rung must go from false to true to make the move operation occur, and is set by either manually typing the number into the register or having your ladder logic move a value into the register.  IT IS NOT NECESSASRY TO USE THIS TAG OR AN EQUAL INSTRUCTION TO SEND COMMANDS TO THE AMCI SMD23E2.  You can replace it with any other condition that makes the rung true, such as a push button on a HMI terminal.
   7: EQU(run_SMD23E2,3)AMCI_SMD23E2_Jog_CCW(AOI_CCW_Jog_Move,buffered_SMD23E2_data[0],CCW_jog_Programmed_Speed,CCW_jog_Acceleration,CCW_jog_Deceleration,AMCI_SMD23E2:O);
   // A Jog move that is occurring will be stopped when the Jog move command bit is reset to zero.  When the SMD23E2 detects this on to off transition of the Jog move command bit, it will reduce the speed at the deceleration parameter value until motion has stopped.
   // When tag run_SMD23E2 is equal to zero, and the CCW_Jog_move_occurring bit is set, reset the driver's command word to zero.   Also unlatch the Add On Instructions Jog_CCW_Occurring bit
   8: EQU(run_SMD23E2,0)XIC(AOI_CCW_Jog_Move.Jog_CCW_Occurring)[MOV(0,AMCI_SMD23E2:O.COMMAND_WORD_0) ,OTU(AOI_CCW_Jog_Move.Jog_CCW_Occurring) ];
   // When register run_SMD23E2 is equal to 4, send the CW Home command to the AMCI SMD23E2.  This command can only be issued if the SMD23E2 has been configured with a home input.  The following conditions will cause a Command Error (Status Word 1 bit 12) to be generated.
   // 1. If the SMD23E2 has not been configured with a home input.
   // 2. If the velocity, acceleration, and deceleration are not valid.
   // WARNING!  Caution must be used when issuing a homing command.  Once started, motion will continue until the home input is reached, an end limit or Emergency Stop Input is reached, or the Immediate Stop Command is issued.  Resetting the command word to zero WILL NOT STOP a home operation.
   // The AXIS_STATUS_BITS field must contain the information from the SMD23E2's first input word, which is Status Word 1.
   // Register run_SMD23E2 is only an internal tag used to illustrate how the rung must go from false to true to make the move operation occur, and is set by either manually typing the number into the register or having your ladder logic move a value into the register.  IT IS NOT NECESSASRY TO USE THIS REGISTER OR AN EQUAL INSTRUCTION TO SEND COMMANDS TO THE AMCI SMD23E2.  You can replace it with any other condition that makes the rung true, such as a push button on a HMI terminal.
   9: EQU(run_SMD23E2,4)AMCI_SMD23E2_Home_CW(AOI_Home_CW,buffered_SMD23E2_data[0],CW_Home_Programmed_Speed,CW_Home_Acceleration,CW_Home_Deceleration,AMCI_SMD23E2:O);
   // When tag run_SMD23E2 is equal to 5, send the Preset Current Motor Position command to the SMD23E2 driver.
   // This command allows you to set the current motor position to any desired value and will also make the position data valid, allowing Absolute Moves to occur.
   // Register run_SMD23E2 is only an internal tag used to illustrate how the rung must go from false to true to make the move operation occur, and is set by either manually typing the number into the register or having your ladder logic move a value into the register.  IT IS NOT NECESSASRY TO USE THIS REGISTER OR AN EQUAL INSTRUCTION TO SEND COMMANDS TO THE AMCI SMD23E2.  You can replace it with any other condition that makes the rung true, such as a push button on a HMI terminal.
   10: EQU(run_SMD23E2,5)AMCI_SMD23E2_Preset_Motor_Position(AOI_Preset_Position,preset_SMD23E2_Target_Position,AMCI_SMD23E2:O);
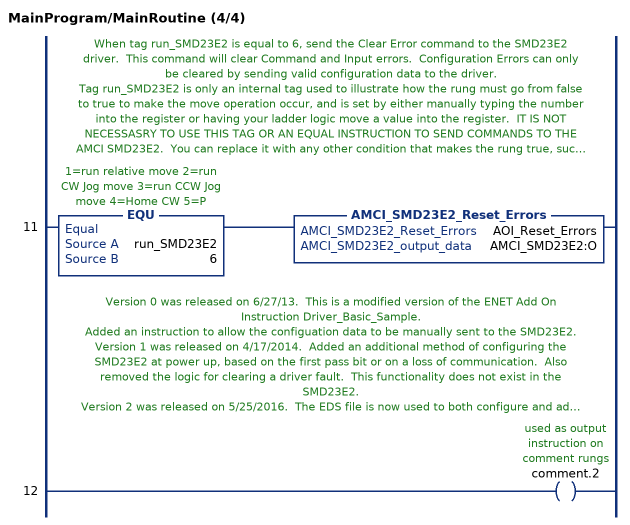
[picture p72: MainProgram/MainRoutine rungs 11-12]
   // When tag run_SMD23E2 is equal to 6, send the Clear Error command to the SMD23E2 driver.  This command will clear Command and Input errors.  Configuration Errors can only be cleared by sending valid configuration data to the driver.
   // Tag run_SMD23E2 is only an internal tag used to illustrate how the rung must go from false to true to make the move operation occur, and is set by either manually typing the number into the register or having your ladder logic move a value into the register.  IT IS NOT NECESSASRY TO USE THIS TAG OR AN EQUAL INSTRUCTION TO SEND COMMANDS TO THE AMCI SMD23E2.  You can replace it with any other condition that makes the rung true, such as a push button on a HMI terminal.
   11: EQU(run_SMD23E2,6)AMCI_SMD23E2_Reset_Errors(AOI_Reset_Errors,AMCI_SMD23E2:O);
   // Version 0 was released on 6/27/13.  This is a modified version of the ENET Add On Instruction Driver_Basic_Sample.
   // Added an instruction to allow the configuation data to be manually sent to the SMD23E2.
   // Version 1 was released on 4/17/2014.  Added an additional method of configuring the SMD23E2 at power up, based on the first pass bit or on a loss of communication.  Also removed the logic for clearing a driver fault.  This functionality does not exist in the SMD23E2.
   // Version 2 was released on 5/25/2016.  The EDS file is now used to both configure and add the SMD23E2 to the network, so the logic to send the configuration data to the driver was removed.  The combine_separate subroutine was  also removed.  The default input and output data format is now straight binary, so the Add On Instructions were changed to take this new format into account.  The Preset Motor Position command rung was changed so that it no longer occurs automaticaly if the posiiton is invalid, and Hold, Resume, Axis Follower, Blend / Assembled Move, and Program Motor Current  AOIs were created.
   // Version 3 was released on 8/16/2016 and added a save in flash field to the Preset_Encoder_Position Add On Instruction.
   // Version 4 was released on 7/6/2017 and modified the absolute, relative, home CW, home CCW, run blend, and run dwell moves Add On Instrucitions so that they would automatically reset the command word to zero when motion is occurring.  Also added EN and ER bits to these AOIs and to the jog, egistration, and follower move AOIs.  Created a circular axis follower and Preset Motor to Encoder AOIs.  The logic that caused the relative mvoe to automatically repeat was also removed.
   // Version 5 was released in 6/2019.   Changed to a L71 PLC and an EN2T module.   Modified the Absolute, Relative, Jog, Home, Registration, run blend / dwell, and axis follower AOIs so that the Error bit will be unlatched if the rung goes false.  Also modified the Absolute, Relative, Jog, Home, and run blend / dwell AOIs with a hidden parameter allowing the programming of the motor current.  Finally modified the Axis Follower commands to by default use the jog CCW command and have an option of the jog CW command.  (The status bits of the jog CCW update faster and the jog CW has smoother motion.)
   12: OTE(comment.2);
END_ROUTINE
END_PROGRAM

PROGRAM SMD23E2_follower_circular   (* main routine SMD23E2_follower_circular *)
VAR
   AOI_Axis_Follower_Circular : AMCI_SMD23E2_Axis_Follower_Circular;
END_VAR

ROUTINE SMD23E2_follower_circular   (* ladder *)
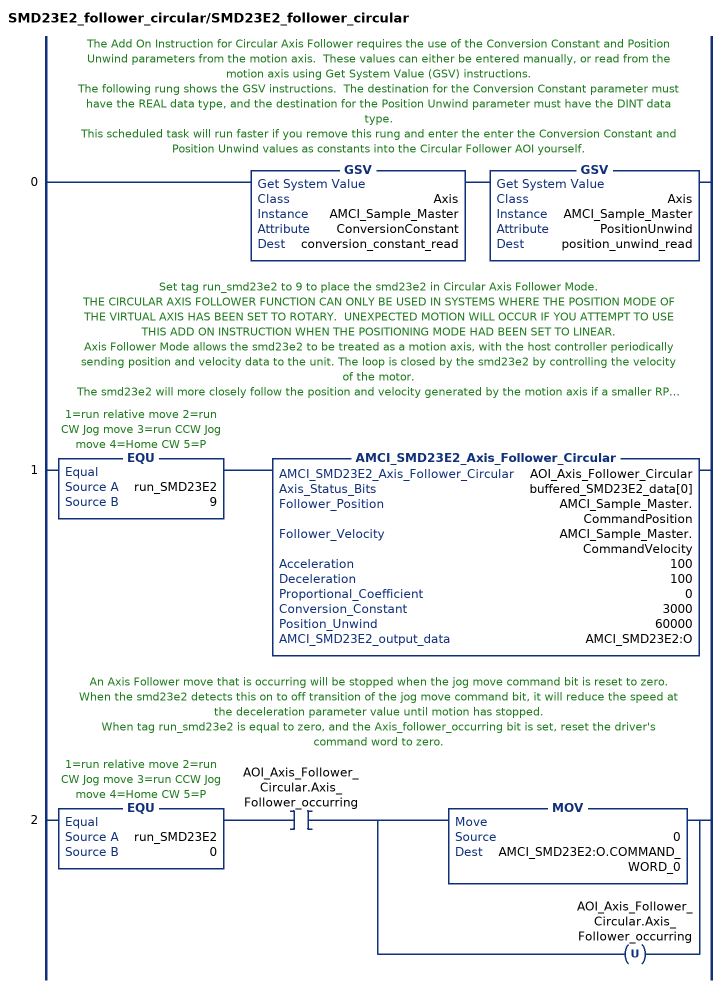
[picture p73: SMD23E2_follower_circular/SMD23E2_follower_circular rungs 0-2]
   // The Add On Instruction for Circular Axis Follower requires the use of the Conversion Constant and Position Unwind parameters from the motion axis.  These values can either be entered manually, or read from the motion axis using Get System Value (GSV) instructions.
   // The following rung shows the GSV instructions.  The destination for the Conversion Constant parameter must have the REAL data type, and the destination for the Position Unwind parameter must have the DINT data type.
   // This scheduled task will run faster if you remove this rung and enter the enter the Conversion Constant and Position Unwind values as constants into the Circular Follower AOI yourself.
   0: GSV(Axis,AMCI_Sample_Master,ConversionConstant,conversion_constant_read)GSV(Axis,AMCI_Sample_Master,PositionUnwind,position_unwind_read);
   // Set tag run_smd23e2 to 9 to place the smd23e2 in Circular Axis Follower Mode.
   // THE CIRCULAR AXIS FOLLOWER FUNCTION CAN ONLY BE USED IN SYSTEMS WHERE THE POSITION MODE OF THE VIRTUAL AXIS HAS BEEN SET TO ROTARY.  UNEXPECTED MOTION WILL OCCUR IF YOU ATTEMPT TO USE THIS ADD ON INSTRUCTION WHEN THE POSITIONING MODE HAD BEEN SET TO LINEAR.
   // Axis Follower Mode allows the smd23e2 to be treated as a motion axis, with the host controller periodically sending position and velocity data to the unit. The loop is closed by the smd23e2 by controlling the velocity of the motor.
   // The smd23e2 will more closely follow the position and velocity generated by the motion axis if a smaller RPI time is used.  The smd23e2’s minimum RPI time is 1.5ms and a value of 2ms is recommended.
   // The following Add On Instruction places the smd23e2 in Circular Axis Follower mode and sends the command data, along with the position and velocity directly from the motion axis, to the smd23e2.  The data also includes the follower type (motor or encoder) acceleration, deceleration, a proportional coefficient, conversion constant, and a position unwind parameter.
   // Axis_Status_Bits:  This is the MSW status word from the smd23e2, and the data contained in this register is used by the Add On Instruction to set the Motion Occurring and ER bits.
   // Follower_Position = REAL DATA TYPE position directly from the motion axis
   // Follower_Velocity = REAL DATA TYPE velocity directly from the motion axis
   // Acceleration and Deceleration = an actual value or an INT DATA TYPE register
   // Proportional Coefficient = an actual value or an INT TYPE register.  A value of 0 to 2 is recommended.
   // Conversion Constant = an actual value or a REAL data type register.   The value in this field is multiplied by the Position and Velocity from the master axis before being sent to the SMD23E2 and scales the supplied position data to the SMD23E2’s motor counts per turn.   This field is typically, but does not have to be, set to the master axis’ Conversion Constant.
   // Position Unwind = an actual value or an INT TYPE register. This field MUST BE SET to the Position Unwind parameter that was entered on the Conversion tab of the motion axis.   The Position Unwind Value MUST BE IN THE RANGE OF 21 TO 65535.
   // BOOL Bit Axis_follower_occurring is a flag to indicate that an axis follower move is occurring.
   // Register run_smd23e2 is only an internal tag used to illustrate how the rung must go from false to true to make the move operation occur, and is set by either manually typing the number into the register or having your ladder logic move a value into the register.  IT IS NOT NECESSASRY TO USE THIS REGISTER OR AN EQUAL INSTRUCTION TO SEND COMMANDS TO THE AMCI smd23e2.  You can replace it with any other condition that makes the rung true, such as a push button on a HMI terminal.
   1: EQU(run_SMD23E2,9)AMCI_SMD23E2_Axis_Follower_Circular(AOI_Axis_Follower_Circular,buffered_SMD23E2_data[0],AMCI_Sample_Master.CommandPosition,AMCI_Sample_Master.CommandVelocity,100,100,0,3000,60000,AMCI_SMD23E2:O);
   // An Axis Follower move that is occurring will be stopped when the jog move command bit is reset to zero.  When the smd23e2 detects this on to off transition of the jog move command bit, it will reduce the speed at the deceleration parameter value until motion has stopped.
   // When tag run_smd23e2 is equal to zero, and the Axis_follower_occurring bit is set, reset the driver's command word to zero.
   2: EQU(run_SMD23E2,0)XIC(AOI_Axis_Follower_Circular.Axis_Follower_occurring)[MOV(0,AMCI_SMD23E2:O.COMMAND_WORD_0) ,OTU(AOI_Axis_Follower_Circular.Axis_Follower_occurring) ];
END_ROUTINE
END_PROGRAM
